VERSION 5.7 ;
  NOWIREEXTENSIONATPIN ON ;
  DIVIDERCHAR "/" ;
  BUSBITCHARS "[]" ;
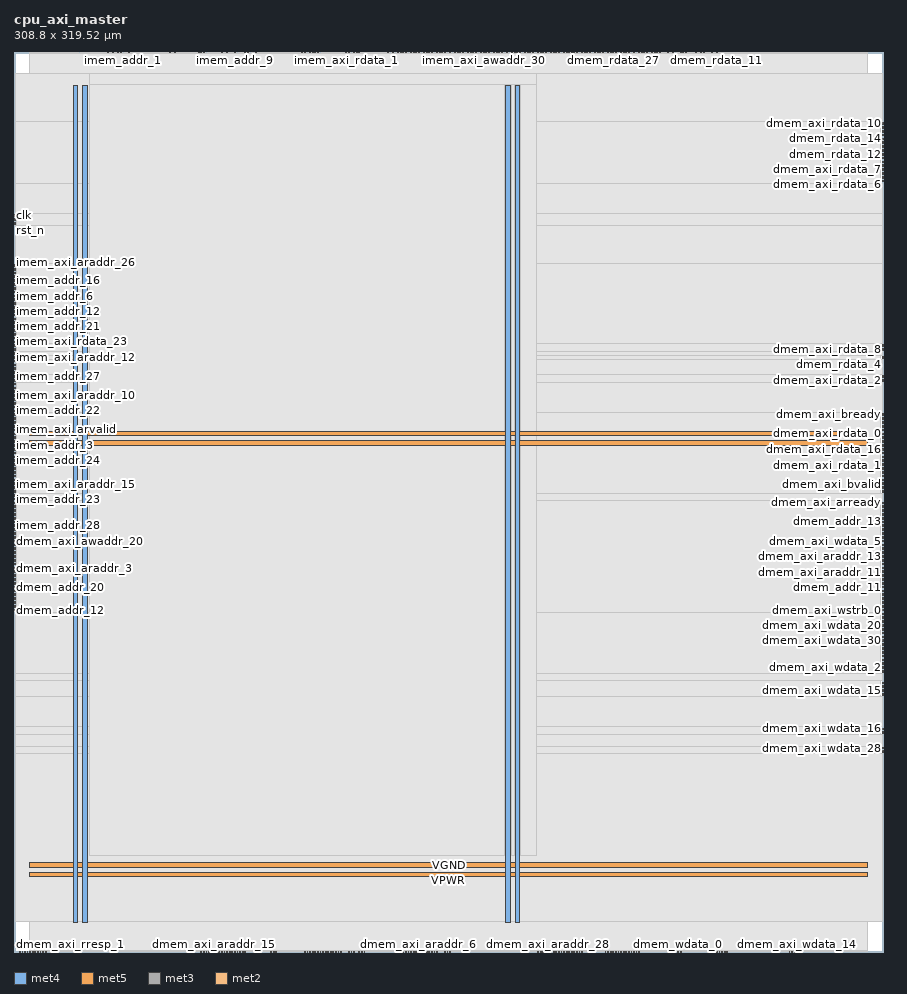
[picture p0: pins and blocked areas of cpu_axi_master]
MACRO cpu_axi_master
  CLASS BLOCK ;
  FOREIGN cpu_axi_master ;
  ORIGIN 0.000 0.000 ;
  SIZE 308.800 BY 319.520 ;
  PIN VGND
    DIRECTION INOUT ;
    USE GROUND ;
    PORT
      LAYER met4 ;
        RECT 24.340 10.640 25.940 307.600 ;
    END
    PORT
      LAYER met4 ;
        RECT 177.940 10.640 179.540 307.600 ;
    END
    PORT
      LAYER met5 ;
        RECT 5.520 30.030 303.140 31.630 ;
    END
    PORT
      LAYER met5 ;
        RECT 5.520 183.210 303.140 184.810 ;
    END
  END VGND
  PIN VPWR
    DIRECTION INOUT ;
    USE POWER ;
    PORT
      LAYER met4 ;
        RECT 21.040 10.640 22.640 307.600 ;
    END
    PORT
      LAYER met4 ;
        RECT 174.640 10.640 176.240 307.600 ;
    END
    PORT
      LAYER met5 ;
        RECT 5.520 26.730 303.140 28.330 ;
    END
    PORT
      LAYER met5 ;
        RECT 5.520 179.910 303.140 181.510 ;
    END
  END VPWR
  PIN clk
    DIRECTION INPUT ;
    USE SIGNAL ;
    ANTENNAGATEAREA 1.286700 ;
    ANTENNADIFFAREA 0.434700 ;
    PORT
      LAYER met3 ;
        RECT 0.000 261.160 0.600 261.760 ;
    END
  END clk
  PIN dmem_addr_0
    DIRECTION INPUT ;
    USE SIGNAL ;
    ANTENNAGATEAREA 0.647700 ;
    ANTENNADIFFAREA 0.434700 ;
    PORT
      LAYER met2 ;
        RECT 115.090 0.000 115.370 0.280 ;
    END
  END dmem_addr_0
  PIN dmem_addr_1
    DIRECTION INPUT ;
    USE SIGNAL ;
    ANTENNAGATEAREA 0.647700 ;
    ANTENNADIFFAREA 0.434700 ;
    PORT
      LAYER met2 ;
        RECT 105.890 0.000 106.170 0.280 ;
    END
  END dmem_addr_1
  PIN dmem_addr_10
    DIRECTION INPUT ;
    USE SIGNAL ;
    ANTENNAGATEAREA 0.647700 ;
    ANTENNADIFFAREA 0.434700 ;
    PORT
      LAYER met2 ;
        RECT 92.090 0.000 92.370 0.280 ;
    END
  END dmem_addr_10
  PIN dmem_addr_11
    DIRECTION INPUT ;
    USE SIGNAL ;
    ANTENNAGATEAREA 0.647700 ;
    ANTENNADIFFAREA 0.434700 ;
    PORT
      LAYER met3 ;
        RECT 308.200 129.240 308.800 129.840 ;
    END
  END dmem_addr_11
  PIN dmem_addr_12
    DIRECTION INPUT ;
    USE SIGNAL ;
    ANTENNAGATEAREA 0.647700 ;
    ANTENNADIFFAREA 0.434700 ;
    PORT
      LAYER met3 ;
        RECT 0.000 121.080 0.600 121.680 ;
    END
  END dmem_addr_12
  PIN dmem_addr_13
    DIRECTION INPUT ;
    USE SIGNAL ;
    ANTENNAGATEAREA 0.647700 ;
    ANTENNADIFFAREA 0.434700 ;
    PORT
      LAYER met3 ;
        RECT 308.200 152.360 308.800 152.960 ;
    END
  END dmem_addr_13
  PIN dmem_addr_14
    DIRECTION INPUT ;
    USE SIGNAL ;
    ANTENNAGATEAREA 0.647700 ;
    ANTENNADIFFAREA 0.434700 ;
    PORT
      LAYER met2 ;
        RECT 66.330 0.000 66.610 0.280 ;
    END
  END dmem_addr_14
  PIN dmem_addr_15
    DIRECTION INPUT ;
    USE SIGNAL ;
    ANTENNAGATEAREA 0.647700 ;
    ANTENNADIFFAREA 0.434700 ;
    PORT
      LAYER met2 ;
        RECT 73.690 0.000 73.970 0.280 ;
    END
  END dmem_addr_15
  PIN dmem_addr_16
    DIRECTION INPUT ;
    USE SIGNAL ;
    ANTENNAGATEAREA 0.647700 ;
    ANTENNADIFFAREA 0.434700 ;
    PORT
      LAYER met2 ;
        RECT 76.450 0.000 76.730 0.280 ;
    END
  END dmem_addr_16
  PIN dmem_addr_17
    DIRECTION INPUT ;
    USE SIGNAL ;
    ANTENNAGATEAREA 0.647700 ;
    ANTENNADIFFAREA 0.434700 ;
    PORT
      LAYER met2 ;
        RECT 109.570 0.000 109.850 0.280 ;
    END
  END dmem_addr_17
  PIN dmem_addr_18
    DIRECTION INPUT ;
    USE SIGNAL ;
    ANTENNAGATEAREA 0.647700 ;
    ANTENNADIFFAREA 0.434700 ;
    PORT
      LAYER met2 ;
        RECT 104.970 0.000 105.250 0.280 ;
    END
  END dmem_addr_18
  PIN dmem_addr_19
    DIRECTION INPUT ;
    USE SIGNAL ;
    ANTENNAGATEAREA 0.647700 ;
    ANTENNADIFFAREA 0.434700 ;
    PORT
      LAYER met2 ;
        RECT 123.370 0.000 123.650 0.280 ;
    END
  END dmem_addr_19
  PIN dmem_addr_2
    DIRECTION INPUT ;
    USE SIGNAL ;
    ANTENNAGATEAREA 0.647700 ;
    ANTENNADIFFAREA 0.434700 ;
    PORT
      LAYER met2 ;
        RECT 141.770 0.000 142.050 0.280 ;
    END
  END dmem_addr_2
  PIN dmem_addr_20
    DIRECTION INPUT ;
    USE SIGNAL ;
    ANTENNAGATEAREA 0.647700 ;
    ANTENNADIFFAREA 0.434700 ;
    PORT
      LAYER met3 ;
        RECT 0.000 129.240 0.600 129.840 ;
    END
  END dmem_addr_20
  PIN dmem_addr_21
    DIRECTION INPUT ;
    USE SIGNAL ;
    ANTENNAGATEAREA 0.647700 ;
    ANTENNADIFFAREA 0.434700 ;
    PORT
      LAYER met2 ;
        RECT 145.450 0.000 145.730 0.280 ;
    END
  END dmem_addr_21
  PIN dmem_addr_22
    DIRECTION INPUT ;
    USE SIGNAL ;
    ANTENNAGATEAREA 0.647700 ;
    ANTENNADIFFAREA 0.434700 ;
    PORT
      LAYER met2 ;
        RECT 137.170 0.000 137.450 0.280 ;
    END
  END dmem_addr_22
  PIN dmem_addr_23
    DIRECTION INPUT ;
    USE SIGNAL ;
    ANTENNAGATEAREA 0.647700 ;
    ANTENNADIFFAREA 0.434700 ;
    PORT
      LAYER met2 ;
        RECT 77.370 0.000 77.650 0.280 ;
    END
  END dmem_addr_23
  PIN dmem_addr_24
    DIRECTION INPUT ;
    USE SIGNAL ;
    ANTENNAGATEAREA 0.647700 ;
    ANTENNADIFFAREA 0.434700 ;
    PORT
      LAYER met2 ;
        RECT 146.370 0.000 146.650 0.280 ;
    END
  END dmem_addr_24
  PIN dmem_addr_25
    DIRECTION INPUT ;
    USE SIGNAL ;
    ANTENNAGATEAREA 0.647700 ;
    ANTENNADIFFAREA 0.434700 ;
    PORT
      LAYER met2 ;
        RECT 119.690 0.000 119.970 0.280 ;
    END
  END dmem_addr_25
  PIN dmem_addr_26
    DIRECTION INPUT ;
    USE SIGNAL ;
    ANTENNAGATEAREA 0.647700 ;
    ANTENNADIFFAREA 0.434700 ;
    PORT
      LAYER met2 ;
        RECT 201.570 0.000 201.850 0.280 ;
    END
  END dmem_addr_26
  PIN dmem_addr_27
    DIRECTION INPUT ;
    USE SIGNAL ;
    ANTENNAGATEAREA 0.647700 ;
    ANTENNADIFFAREA 0.434700 ;
    PORT
      LAYER met2 ;
        RECT 194.210 0.000 194.490 0.280 ;
    END
  END dmem_addr_27
  PIN dmem_addr_28
    DIRECTION INPUT ;
    USE SIGNAL ;
    ANTENNAGATEAREA 0.647700 ;
    ANTENNADIFFAREA 0.434700 ;
    PORT
      LAYER met2 ;
        RECT 188.690 0.000 188.970 0.280 ;
    END
  END dmem_addr_28
  PIN dmem_addr_29
    DIRECTION INPUT ;
    USE SIGNAL ;
    ANTENNAGATEAREA 0.647700 ;
    ANTENNADIFFAREA 0.434700 ;
    PORT
      LAYER met2 ;
        RECT 199.730 0.000 200.010 0.280 ;
    END
  END dmem_addr_29
  PIN dmem_addr_3
    DIRECTION INPUT ;
    USE SIGNAL ;
    ANTENNAGATEAREA 0.647700 ;
    ANTENNADIFFAREA 0.434700 ;
    PORT
      LAYER met3 ;
        RECT 0.000 130.600 0.600 131.200 ;
    END
  END dmem_addr_3
  PIN dmem_addr_30
    DIRECTION INPUT ;
    USE SIGNAL ;
    ANTENNAGATEAREA 0.647700 ;
    ANTENNADIFFAREA 0.434700 ;
    PORT
      LAYER met2 ;
        RECT 200.650 0.000 200.930 0.280 ;
    END
  END dmem_addr_30
  PIN dmem_addr_31
    DIRECTION INPUT ;
    USE SIGNAL ;
    ANTENNAGATEAREA 0.647700 ;
    ANTENNADIFFAREA 0.434700 ;
    PORT
      LAYER met2 ;
        RECT 187.770 0.000 188.050 0.280 ;
    END
  END dmem_addr_31
  PIN dmem_addr_4
    DIRECTION INPUT ;
    USE SIGNAL ;
    ANTENNAGATEAREA 0.647700 ;
    ANTENNADIFFAREA 0.434700 ;
    PORT
      LAYER met2 ;
        RECT 75.530 0.000 75.810 0.280 ;
    END
  END dmem_addr_4
  PIN dmem_addr_5
    DIRECTION INPUT ;
    USE SIGNAL ;
    ANTENNAGATEAREA 0.647700 ;
    ANTENNADIFFAREA 0.434700 ;
    PORT
      LAYER met2 ;
        RECT 80.130 0.000 80.410 0.280 ;
    END
  END dmem_addr_5
  PIN dmem_addr_6
    DIRECTION INPUT ;
    USE SIGNAL ;
    ANTENNAGATEAREA 0.647700 ;
    ANTENNADIFFAREA 0.434700 ;
    PORT
      LAYER met2 ;
        RECT 142.690 0.000 142.970 0.280 ;
    END
  END dmem_addr_6
  PIN dmem_addr_7
    DIRECTION INPUT ;
    USE SIGNAL ;
    ANTENNAGATEAREA 0.647700 ;
    ANTENNADIFFAREA 0.434700 ;
    PORT
      LAYER met2 ;
        RECT 110.490 0.000 110.770 0.280 ;
    END
  END dmem_addr_7
  PIN dmem_addr_8
    DIRECTION INPUT ;
    USE SIGNAL ;
    ANTENNAGATEAREA 0.647700 ;
    ANTENNADIFFAREA 0.434700 ;
    PORT
      LAYER met3 ;
        RECT 0.000 123.800 0.600 124.400 ;
    END
  END dmem_addr_8
  PIN dmem_addr_9
    DIRECTION INPUT ;
    USE SIGNAL ;
    ANTENNAGATEAREA 0.647700 ;
    ANTENNADIFFAREA 0.434700 ;
    PORT
      LAYER met2 ;
        RECT 153.730 0.000 154.010 0.280 ;
    END
  END dmem_addr_9
  PIN dmem_axi_araddr_0
    DIRECTION OUTPUT ;
    USE SIGNAL ;
    ANTENNAGATEAREA 0.434700 ;
    ANTENNADIFFAREA 1.137600 ;
    PORT
      LAYER met2 ;
        RECT 114.170 0.000 114.450 0.280 ;
    END
  END dmem_axi_araddr_0
  PIN dmem_axi_araddr_1
    DIRECTION OUTPUT ;
    USE SIGNAL ;
    ANTENNAGATEAREA 0.434700 ;
    ANTENNADIFFAREA 1.137600 ;
    PORT
      LAYER met2 ;
        RECT 106.810 0.000 107.090 0.280 ;
    END
  END dmem_axi_araddr_1
  PIN dmem_axi_araddr_10
    DIRECTION OUTPUT ;
    USE SIGNAL ;
    ANTENNAGATEAREA 0.434700 ;
    ANTENNADIFFAREA 1.137600 ;
    PORT
      LAYER met2 ;
        RECT 91.170 0.000 91.450 0.280 ;
    END
  END dmem_axi_araddr_10
  PIN dmem_axi_araddr_11
    DIRECTION OUTPUT ;
    USE SIGNAL ;
    ANTENNAGATEAREA 0.434700 ;
    ANTENNADIFFAREA 1.137600 ;
    PORT
      LAYER met3 ;
        RECT 308.200 131.960 308.800 132.560 ;
    END
  END dmem_axi_araddr_11
  PIN dmem_axi_araddr_12
    DIRECTION OUTPUT ;
    USE SIGNAL ;
    ANTENNAGATEAREA 0.434700 ;
    ANTENNADIFFAREA 1.137600 ;
    PORT
      LAYER met3 ;
        RECT 0.000 125.160 0.600 125.760 ;
    END
  END dmem_axi_araddr_12
  PIN dmem_axi_araddr_13
    DIRECTION OUTPUT ;
    USE SIGNAL ;
    ANTENNAGATEAREA 0.434700 ;
    ANTENNADIFFAREA 1.137600 ;
    PORT
      LAYER met3 ;
        RECT 308.200 140.120 308.800 140.720 ;
    END
  END dmem_axi_araddr_13
  PIN dmem_axi_araddr_14
    DIRECTION OUTPUT ;
    USE SIGNAL ;
    ANTENNAGATEAREA 0.434700 ;
    ANTENNADIFFAREA 1.137600 ;
    PORT
      LAYER met2 ;
        RECT 67.250 0.000 67.530 0.280 ;
    END
  END dmem_axi_araddr_14
  PIN dmem_axi_araddr_15
    DIRECTION OUTPUT ;
    USE SIGNAL ;
    ANTENNAGATEAREA 0.434700 ;
    ANTENNADIFFAREA 1.137600 ;
    PORT
      LAYER met2 ;
        RECT 70.930 0.000 71.210 0.280 ;
    END
  END dmem_axi_araddr_15
  PIN dmem_axi_araddr_16
    DIRECTION OUTPUT ;
    USE SIGNAL ;
    ANTENNAGATEAREA 0.434700 ;
    ANTENNADIFFAREA 1.137600 ;
    PORT
      LAYER met2 ;
        RECT 69.090 0.000 69.370 0.280 ;
    END
  END dmem_axi_araddr_16
  PIN dmem_axi_araddr_17
    DIRECTION OUTPUT ;
    USE SIGNAL ;
    ANTENNAGATEAREA 0.434700 ;
    ANTENNADIFFAREA 1.137600 ;
    PORT
      LAYER met2 ;
        RECT 111.410 0.000 111.690 0.280 ;
    END
  END dmem_axi_araddr_17
  PIN dmem_axi_araddr_18
    DIRECTION OUTPUT ;
    USE SIGNAL ;
    ANTENNAGATEAREA 0.434700 ;
    ANTENNADIFFAREA 1.137600 ;
    PORT
      LAYER met2 ;
        RECT 103.130 0.000 103.410 0.280 ;
    END
  END dmem_axi_araddr_18
  PIN dmem_axi_araddr_19
    DIRECTION OUTPUT ;
    USE SIGNAL ;
    ANTENNAGATEAREA 0.434700 ;
    ANTENNADIFFAREA 1.137600 ;
    PORT
      LAYER met2 ;
        RECT 124.290 0.000 124.570 0.280 ;
    END
  END dmem_axi_araddr_19
  PIN dmem_axi_araddr_2
    DIRECTION OUTPUT ;
    USE SIGNAL ;
    ANTENNAGATEAREA 0.434700 ;
    ANTENNADIFFAREA 1.137600 ;
    PORT
      LAYER met2 ;
        RECT 140.850 0.000 141.130 0.280 ;
    END
  END dmem_axi_araddr_2
  PIN dmem_axi_araddr_20
    DIRECTION OUTPUT ;
    USE SIGNAL ;
    ANTENNAGATEAREA 0.434700 ;
    ANTENNADIFFAREA 1.137600 ;
    PORT
      LAYER met3 ;
        RECT 0.000 144.200 0.600 144.800 ;
    END
  END dmem_axi_araddr_20
  PIN dmem_axi_araddr_21
    DIRECTION OUTPUT ;
    USE SIGNAL ;
    ANTENNAGATEAREA 0.434700 ;
    ANTENNADIFFAREA 1.137600 ;
    PORT
      LAYER met2 ;
        RECT 150.050 0.000 150.330 0.280 ;
    END
  END dmem_axi_araddr_21
  PIN dmem_axi_araddr_22
    DIRECTION OUTPUT ;
    USE SIGNAL ;
    ANTENNAGATEAREA 0.434700 ;
    ANTENNADIFFAREA 1.137600 ;
    PORT
      LAYER met2 ;
        RECT 138.090 0.000 138.370 0.280 ;
    END
  END dmem_axi_araddr_22
  PIN dmem_axi_araddr_23
    DIRECTION OUTPUT ;
    USE SIGNAL ;
    ANTENNAGATEAREA 0.434700 ;
    ANTENNADIFFAREA 1.137600 ;
    PORT
      LAYER met2 ;
        RECT 78.290 0.000 78.570 0.280 ;
    END
  END dmem_axi_araddr_23
  PIN dmem_axi_araddr_24
    DIRECTION OUTPUT ;
    USE SIGNAL ;
    ANTENNAGATEAREA 0.434700 ;
    ANTENNADIFFAREA 1.137600 ;
    PORT
      LAYER met2 ;
        RECT 149.130 0.000 149.410 0.280 ;
    END
  END dmem_axi_araddr_24
  PIN dmem_axi_araddr_25
    DIRECTION OUTPUT ;
    USE SIGNAL ;
    ANTENNAGATEAREA 0.434700 ;
    ANTENNADIFFAREA 1.137600 ;
    PORT
      LAYER met2 ;
        RECT 120.610 0.000 120.890 0.280 ;
    END
  END dmem_axi_araddr_25
  PIN dmem_axi_araddr_26
    DIRECTION OUTPUT ;
    USE SIGNAL ;
    ANTENNAGATEAREA 0.434700 ;
    ANTENNADIFFAREA 1.137600 ;
    PORT
      LAYER met2 ;
        RECT 186.850 0.000 187.130 0.280 ;
    END
  END dmem_axi_araddr_26
  PIN dmem_axi_araddr_27
    DIRECTION OUTPUT ;
    USE SIGNAL ;
    ANTENNAGATEAREA 0.434700 ;
    ANTENNADIFFAREA 1.137600 ;
    PORT
      LAYER met2 ;
        RECT 196.050 0.000 196.330 0.280 ;
    END
  END dmem_axi_araddr_27
  PIN dmem_axi_araddr_28
    DIRECTION OUTPUT ;
    USE SIGNAL ;
    ANTENNAGATEAREA 0.434700 ;
    ANTENNADIFFAREA 1.137600 ;
    PORT
      LAYER met2 ;
        RECT 189.610 0.000 189.890 0.280 ;
    END
  END dmem_axi_araddr_28
  PIN dmem_axi_araddr_29
    DIRECTION OUTPUT ;
    USE SIGNAL ;
    ANTENNAGATEAREA 0.434700 ;
    ANTENNADIFFAREA 1.137600 ;
    PORT
      LAYER met2 ;
        RECT 185.930 0.000 186.210 0.280 ;
    END
  END dmem_axi_araddr_29
  PIN dmem_axi_araddr_3
    DIRECTION OUTPUT ;
    USE SIGNAL ;
    ANTENNAGATEAREA 0.434700 ;
    ANTENNADIFFAREA 1.137600 ;
    PORT
      LAYER met3 ;
        RECT 0.000 133.320 0.600 133.920 ;
    END
  END dmem_axi_araddr_3
  PIN dmem_axi_araddr_30
    DIRECTION OUTPUT ;
    USE SIGNAL ;
    ANTENNAGATEAREA 0.434700 ;
    ANTENNADIFFAREA 1.137600 ;
    PORT
      LAYER met2 ;
        RECT 190.530 0.000 190.810 0.280 ;
    END
  END dmem_axi_araddr_30
  PIN dmem_axi_araddr_31
    DIRECTION OUTPUT ;
    USE SIGNAL ;
    ANTENNAGATEAREA 0.434700 ;
    ANTENNADIFFAREA 1.137600 ;
    PORT
      LAYER met2 ;
        RECT 196.970 0.000 197.250 0.280 ;
    END
  END dmem_axi_araddr_31
  PIN dmem_axi_araddr_4
    DIRECTION OUTPUT ;
    USE SIGNAL ;
    ANTENNAGATEAREA 0.434700 ;
    ANTENNADIFFAREA 1.137600 ;
    PORT
      LAYER met2 ;
        RECT 72.770 0.000 73.050 0.280 ;
    END
  END dmem_axi_araddr_4
  PIN dmem_axi_araddr_5
    DIRECTION OUTPUT ;
    USE SIGNAL ;
    ANTENNAGATEAREA 0.434700 ;
    ANTENNADIFFAREA 1.137600 ;
    PORT
      LAYER met2 ;
        RECT 81.970 0.000 82.250 0.280 ;
    END
  END dmem_axi_araddr_5
  PIN dmem_axi_araddr_6
    DIRECTION OUTPUT ;
    USE SIGNAL ;
    ANTENNAGATEAREA 0.434700 ;
    ANTENNADIFFAREA 1.137600 ;
    PORT
      LAYER met2 ;
        RECT 143.610 0.000 143.890 0.280 ;
    END
  END dmem_axi_araddr_6
  PIN dmem_axi_araddr_7
    DIRECTION OUTPUT ;
    USE SIGNAL ;
    ANTENNAGATEAREA 0.434700 ;
    ANTENNADIFFAREA 1.137600 ;
    PORT
      LAYER met2 ;
        RECT 112.330 0.000 112.610 0.280 ;
    END
  END dmem_axi_araddr_7
  PIN dmem_axi_araddr_8
    DIRECTION OUTPUT ;
    USE SIGNAL ;
    ANTENNAGATEAREA 0.434700 ;
    ANTENNADIFFAREA 1.137600 ;
    PORT
      LAYER met3 ;
        RECT 0.000 136.040 0.600 136.640 ;
    END
  END dmem_axi_araddr_8
  PIN dmem_axi_araddr_9
    DIRECTION OUTPUT ;
    USE SIGNAL ;
    ANTENNAGATEAREA 0.434700 ;
    ANTENNADIFFAREA 1.137600 ;
    PORT
      LAYER met2 ;
        RECT 152.810 0.000 153.090 0.280 ;
    END
  END dmem_axi_araddr_9
  PIN dmem_axi_arready
    DIRECTION INPUT ;
    USE SIGNAL ;
    ANTENNAGATEAREA 0.647700 ;
    ANTENNADIFFAREA 0.434700 ;
    PORT
      LAYER met3 ;
        RECT 308.200 159.160 308.800 159.760 ;
    END
  END dmem_axi_arready
  PIN dmem_axi_arvalid
    DIRECTION OUTPUT ;
    USE SIGNAL ;
    ANTENNAGATEAREA 0.434700 ;
    ANTENNADIFFAREA 1.137600 ;
    PORT
      LAYER met3 ;
        RECT 308.200 157.800 308.800 158.400 ;
    END
  END dmem_axi_arvalid
  PIN dmem_axi_awaddr_0
    DIRECTION OUTPUT ;
    USE SIGNAL ;
    ANTENNAGATEAREA 0.434700 ;
    ANTENNADIFFAREA 1.137600 ;
    PORT
      LAYER met2 ;
        RECT 116.010 0.000 116.290 0.280 ;
    END
  END dmem_axi_awaddr_0
  PIN dmem_axi_awaddr_1
    DIRECTION OUTPUT ;
    USE SIGNAL ;
    ANTENNAGATEAREA 0.434700 ;
    ANTENNADIFFAREA 1.137600 ;
    PORT
      LAYER met2 ;
        RECT 107.730 0.000 108.010 0.280 ;
    END
  END dmem_axi_awaddr_1
  PIN dmem_axi_awaddr_10
    DIRECTION OUTPUT ;
    USE SIGNAL ;
    ANTENNAGATEAREA 0.434700 ;
    ANTENNADIFFAREA 1.137600 ;
    PORT
      LAYER met2 ;
        RECT 93.010 0.000 93.290 0.280 ;
    END
  END dmem_axi_awaddr_10
  PIN dmem_axi_awaddr_11
    DIRECTION OUTPUT ;
    USE SIGNAL ;
    ANTENNAGATEAREA 0.434700 ;
    ANTENNADIFFAREA 1.137600 ;
    PORT
      LAYER met3 ;
        RECT 308.200 130.600 308.800 131.200 ;
    END
  END dmem_axi_awaddr_11
  PIN dmem_axi_awaddr_12
    DIRECTION OUTPUT ;
    USE SIGNAL ;
    ANTENNAGATEAREA 0.434700 ;
    ANTENNADIFFAREA 1.137600 ;
    PORT
      LAYER met3 ;
        RECT 0.000 126.520 0.600 127.120 ;
    END
  END dmem_axi_awaddr_12
  PIN dmem_axi_awaddr_13
    DIRECTION OUTPUT ;
    USE SIGNAL ;
    ANTENNAGATEAREA 0.434700 ;
    ANTENNADIFFAREA 1.137600 ;
    PORT
      LAYER met3 ;
        RECT 308.200 138.760 308.800 139.360 ;
    END
  END dmem_axi_awaddr_13
  PIN dmem_axi_awaddr_14
    DIRECTION OUTPUT ;
    USE SIGNAL ;
    ANTENNAGATEAREA 0.434700 ;
    ANTENNADIFFAREA 1.137600 ;
    PORT
      LAYER met2 ;
        RECT 68.170 0.000 68.450 0.280 ;
    END
  END dmem_axi_awaddr_14
  PIN dmem_axi_awaddr_15
    DIRECTION OUTPUT ;
    USE SIGNAL ;
    ANTENNAGATEAREA 0.434700 ;
    ANTENNADIFFAREA 1.137600 ;
    PORT
      LAYER met2 ;
        RECT 70.010 0.000 70.290 0.280 ;
    END
  END dmem_axi_awaddr_15
  PIN dmem_axi_awaddr_16
    DIRECTION OUTPUT ;
    USE SIGNAL ;
    ANTENNAGATEAREA 0.434700 ;
    ANTENNADIFFAREA 1.137600 ;
    PORT
      LAYER met2 ;
        RECT 71.850 0.000 72.130 0.280 ;
    END
  END dmem_axi_awaddr_16
  PIN dmem_axi_awaddr_17
    DIRECTION OUTPUT ;
    USE SIGNAL ;
    ANTENNAGATEAREA 0.434700 ;
    ANTENNADIFFAREA 1.137600 ;
    PORT
      LAYER met2 ;
        RECT 108.650 0.000 108.930 0.280 ;
    END
  END dmem_axi_awaddr_17
  PIN dmem_axi_awaddr_18
    DIRECTION OUTPUT ;
    USE SIGNAL ;
    ANTENNAGATEAREA 0.434700 ;
    ANTENNADIFFAREA 1.137600 ;
    PORT
      LAYER met2 ;
        RECT 104.050 0.000 104.330 0.280 ;
    END
  END dmem_axi_awaddr_18
  PIN dmem_axi_awaddr_19
    DIRECTION OUTPUT ;
    USE SIGNAL ;
    ANTENNAGATEAREA 0.434700 ;
    ANTENNADIFFAREA 1.137600 ;
    PORT
      LAYER met2 ;
        RECT 122.450 0.000 122.730 0.280 ;
    END
  END dmem_axi_awaddr_19
  PIN dmem_axi_awaddr_2
    DIRECTION OUTPUT ;
    USE SIGNAL ;
    ANTENNAGATEAREA 0.434700 ;
    ANTENNADIFFAREA 1.137600 ;
    PORT
      LAYER met2 ;
        RECT 139.930 0.000 140.210 0.280 ;
    END
  END dmem_axi_awaddr_2
  PIN dmem_axi_awaddr_20
    DIRECTION OUTPUT ;
    USE SIGNAL ;
    ANTENNAGATEAREA 0.434700 ;
    ANTENNADIFFAREA 1.137600 ;
    PORT
      LAYER met3 ;
        RECT 0.000 145.560 0.600 146.160 ;
    END
  END dmem_axi_awaddr_20
  PIN dmem_axi_awaddr_21
    DIRECTION OUTPUT ;
    USE SIGNAL ;
    ANTENNAGATEAREA 0.434700 ;
    ANTENNADIFFAREA 1.137600 ;
    PORT
      LAYER met2 ;
        RECT 147.290 0.000 147.570 0.280 ;
    END
  END dmem_axi_awaddr_21
  PIN dmem_axi_awaddr_22
    DIRECTION OUTPUT ;
    USE SIGNAL ;
    ANTENNAGATEAREA 0.434700 ;
    ANTENNADIFFAREA 1.137600 ;
    PORT
      LAYER met2 ;
        RECT 139.010 0.000 139.290 0.280 ;
    END
  END dmem_axi_awaddr_22
  PIN dmem_axi_awaddr_23
    DIRECTION OUTPUT ;
    USE SIGNAL ;
    ANTENNAGATEAREA 0.434700 ;
    ANTENNADIFFAREA 1.137600 ;
    PORT
      LAYER met2 ;
        RECT 79.210 0.000 79.490 0.280 ;
    END
  END dmem_axi_awaddr_23
  PIN dmem_axi_awaddr_24
    DIRECTION OUTPUT ;
    USE SIGNAL ;
    ANTENNAGATEAREA 0.434700 ;
    ANTENNADIFFAREA 1.137600 ;
    PORT
      LAYER met2 ;
        RECT 148.210 0.000 148.490 0.280 ;
    END
  END dmem_axi_awaddr_24
  PIN dmem_axi_awaddr_25
    DIRECTION OUTPUT ;
    USE SIGNAL ;
    ANTENNAGATEAREA 0.434700 ;
    ANTENNADIFFAREA 1.137600 ;
    PORT
      LAYER met2 ;
        RECT 118.770 0.000 119.050 0.280 ;
    END
  END dmem_axi_awaddr_25
  PIN dmem_axi_awaddr_26
    DIRECTION OUTPUT ;
    USE SIGNAL ;
    ANTENNAGATEAREA 0.434700 ;
    ANTENNADIFFAREA 1.137600 ;
    PORT
      LAYER met2 ;
        RECT 191.450 0.000 191.730 0.280 ;
    END
  END dmem_axi_awaddr_26
  PIN dmem_axi_awaddr_27
    DIRECTION OUTPUT ;
    USE SIGNAL ;
    ANTENNAGATEAREA 0.434700 ;
    ANTENNADIFFAREA 1.137600 ;
    PORT
      LAYER met2 ;
        RECT 192.370 0.000 192.650 0.280 ;
    END
  END dmem_axi_awaddr_27
  PIN dmem_axi_awaddr_28
    DIRECTION OUTPUT ;
    USE SIGNAL ;
    ANTENNAGATEAREA 0.434700 ;
    ANTENNADIFFAREA 1.137600 ;
    PORT
      LAYER met2 ;
        RECT 197.890 0.000 198.170 0.280 ;
    END
  END dmem_axi_awaddr_28
  PIN dmem_axi_awaddr_29
    DIRECTION OUTPUT ;
    USE SIGNAL ;
    ANTENNAGATEAREA 0.434700 ;
    ANTENNADIFFAREA 1.137600 ;
    PORT
      LAYER met2 ;
        RECT 195.130 0.000 195.410 0.280 ;
    END
  END dmem_axi_awaddr_29
  PIN dmem_axi_awaddr_3
    DIRECTION OUTPUT ;
    USE SIGNAL ;
    ANTENNAGATEAREA 0.434700 ;
    ANTENNADIFFAREA 1.137600 ;
    PORT
      LAYER met3 ;
        RECT 0.000 134.680 0.600 135.280 ;
    END
  END dmem_axi_awaddr_3
  PIN dmem_axi_awaddr_30
    DIRECTION OUTPUT ;
    USE SIGNAL ;
    ANTENNAGATEAREA 0.434700 ;
    ANTENNADIFFAREA 1.137600 ;
    PORT
      LAYER met2 ;
        RECT 193.290 0.000 193.570 0.280 ;
    END
  END dmem_axi_awaddr_30
  PIN dmem_axi_awaddr_31
    DIRECTION OUTPUT ;
    USE SIGNAL ;
    ANTENNAGATEAREA 0.434700 ;
    ANTENNADIFFAREA 1.137600 ;
    PORT
      LAYER met2 ;
        RECT 198.810 0.000 199.090 0.280 ;
    END
  END dmem_axi_awaddr_31
  PIN dmem_axi_awaddr_4
    DIRECTION OUTPUT ;
    USE SIGNAL ;
    ANTENNAGATEAREA 0.434700 ;
    ANTENNADIFFAREA 1.137600 ;
    PORT
      LAYER met2 ;
        RECT 74.610 0.000 74.890 0.280 ;
    END
  END dmem_axi_awaddr_4
  PIN dmem_axi_awaddr_5
    DIRECTION OUTPUT ;
    USE SIGNAL ;
    ANTENNAGATEAREA 0.434700 ;
    ANTENNADIFFAREA 1.137600 ;
    PORT
      LAYER met2 ;
        RECT 81.050 0.000 81.330 0.280 ;
    END
  END dmem_axi_awaddr_5
  PIN dmem_axi_awaddr_6
    DIRECTION OUTPUT ;
    USE SIGNAL ;
    ANTENNAGATEAREA 0.434700 ;
    ANTENNADIFFAREA 1.137600 ;
    PORT
      LAYER met2 ;
        RECT 144.530 0.000 144.810 0.280 ;
    END
  END dmem_axi_awaddr_6
  PIN dmem_axi_awaddr_7
    DIRECTION OUTPUT ;
    USE SIGNAL ;
    ANTENNAGATEAREA 0.434700 ;
    ANTENNADIFFAREA 1.137600 ;
    PORT
      LAYER met2 ;
        RECT 113.250 0.000 113.530 0.280 ;
    END
  END dmem_axi_awaddr_7
  PIN dmem_axi_awaddr_8
    DIRECTION OUTPUT ;
    USE SIGNAL ;
    ANTENNAGATEAREA 0.434700 ;
    ANTENNADIFFAREA 1.137600 ;
    PORT
      LAYER met3 ;
        RECT 0.000 138.760 0.600 139.360 ;
    END
  END dmem_axi_awaddr_8
  PIN dmem_axi_awaddr_9
    DIRECTION OUTPUT ;
    USE SIGNAL ;
    ANTENNAGATEAREA 0.434700 ;
    ANTENNADIFFAREA 1.137600 ;
    PORT
      LAYER met2 ;
        RECT 154.650 0.000 154.930 0.280 ;
    END
  END dmem_axi_awaddr_9
  PIN dmem_axi_awready
    DIRECTION INPUT ;
    USE SIGNAL ;
    ANTENNAGATEAREA 0.647700 ;
    ANTENNADIFFAREA 0.434700 ;
    PORT
      LAYER met3 ;
        RECT 308.200 153.720 308.800 154.320 ;
    END
  END dmem_axi_awready
  PIN dmem_axi_awvalid
    DIRECTION OUTPUT ;
    USE SIGNAL ;
    ANTENNAGATEAREA 0.434700 ;
    ANTENNADIFFAREA 1.137600 ;
    PORT
      LAYER met3 ;
        RECT 308.200 155.080 308.800 155.680 ;
    END
  END dmem_axi_awvalid
  PIN dmem_axi_bready
    DIRECTION OUTPUT ;
    USE SIGNAL ;
    ANTENNAGATEAREA 0.434700 ;
    ANTENNADIFFAREA 1.137600 ;
    PORT
      LAYER met3 ;
        RECT 308.200 190.440 308.800 191.040 ;
    END
  END dmem_axi_bready
  PIN dmem_axi_bresp_0
    DIRECTION INPUT ;
    USE SIGNAL ;
    PORT
      LAYER met2 ;
        RECT 1.930 0.000 2.210 0.280 ;
    END
  END dmem_axi_bresp_0
  PIN dmem_axi_bresp_1
    DIRECTION INPUT ;
    USE SIGNAL ;
    PORT
      LAYER met2 ;
        RECT 2.850 0.000 3.130 0.280 ;
    END
  END dmem_axi_bresp_1
  PIN dmem_axi_bvalid
    DIRECTION INPUT ;
    USE SIGNAL ;
    ANTENNAGATEAREA 0.647700 ;
    ANTENNADIFFAREA 0.434700 ;
    PORT
      LAYER met3 ;
        RECT 308.200 163.240 308.800 163.840 ;
    END
  END dmem_axi_bvalid
  PIN dmem_axi_rdata_0
    DIRECTION INPUT ;
    USE SIGNAL ;
    ANTENNAGATEAREA 0.647700 ;
    ANTENNADIFFAREA 0.434700 ;
    PORT
      LAYER met3 ;
        RECT 308.200 186.360 308.800 186.960 ;
    END
  END dmem_axi_rdata_0
  PIN dmem_axi_rdata_1
    DIRECTION INPUT ;
    USE SIGNAL ;
    ANTENNAGATEAREA 0.647700 ;
    ANTENNADIFFAREA 0.434700 ;
    PORT
      LAYER met3 ;
        RECT 308.200 170.040 308.800 170.640 ;
    END
  END dmem_axi_rdata_1
  PIN dmem_axi_rdata_10
    DIRECTION INPUT ;
    USE SIGNAL ;
    ANTENNAGATEAREA 0.647700 ;
    ANTENNADIFFAREA 0.434700 ;
    PORT
      LAYER met3 ;
        RECT 308.200 293.800 308.800 294.400 ;
    END
  END dmem_axi_rdata_10
  PIN dmem_axi_rdata_11
    DIRECTION INPUT ;
    USE SIGNAL ;
    ANTENNAGATEAREA 0.647700 ;
    ANTENNADIFFAREA 0.434700 ;
    PORT
      LAYER met2 ;
        RECT 247.570 319.240 247.850 319.520 ;
    END
  END dmem_axi_rdata_11
  PIN dmem_axi_rdata_12
    DIRECTION INPUT ;
    USE SIGNAL ;
    ANTENNAGATEAREA 0.647700 ;
    ANTENNADIFFAREA 0.434700 ;
    PORT
      LAYER met3 ;
        RECT 308.200 285.640 308.800 286.240 ;
    END
  END dmem_axi_rdata_12
  PIN dmem_axi_rdata_13
    DIRECTION INPUT ;
    USE SIGNAL ;
    ANTENNAGATEAREA 0.647700 ;
    ANTENNADIFFAREA 0.434700 ;
    PORT
      LAYER met3 ;
        RECT 308.200 284.280 308.800 284.880 ;
    END
  END dmem_axi_rdata_13
  PIN dmem_axi_rdata_14
    DIRECTION INPUT ;
    USE SIGNAL ;
    ANTENNAGATEAREA 0.647700 ;
    ANTENNADIFFAREA 0.434700 ;
    PORT
      LAYER met3 ;
        RECT 308.200 287.000 308.800 287.600 ;
    END
  END dmem_axi_rdata_14
  PIN dmem_axi_rdata_15
    DIRECTION INPUT ;
    USE SIGNAL ;
    ANTENNAGATEAREA 0.647700 ;
    ANTENNADIFFAREA 0.434700 ;
    PORT
      LAYER met3 ;
        RECT 308.200 278.840 308.800 279.440 ;
    END
  END dmem_axi_rdata_15
  PIN dmem_axi_rdata_16
    DIRECTION INPUT ;
    USE SIGNAL ;
    ANTENNAGATEAREA 0.647700 ;
    ANTENNADIFFAREA 0.434700 ;
    PORT
      LAYER met3 ;
        RECT 308.200 175.480 308.800 176.080 ;
    END
  END dmem_axi_rdata_16
  PIN dmem_axi_rdata_17
    DIRECTION INPUT ;
    USE SIGNAL ;
    ANTENNAGATEAREA 0.647700 ;
    ANTENNADIFFAREA 0.434700 ;
    PORT
      LAYER met3 ;
        RECT 308.200 164.600 308.800 165.200 ;
    END
  END dmem_axi_rdata_17
  PIN dmem_axi_rdata_18
    DIRECTION INPUT ;
    USE SIGNAL ;
    ANTENNAGATEAREA 0.647700 ;
    ANTENNADIFFAREA 0.434700 ;
    PORT
      LAYER met3 ;
        RECT 308.200 185.000 308.800 185.600 ;
    END
  END dmem_axi_rdata_18
  PIN dmem_axi_rdata_19
    DIRECTION INPUT ;
    USE SIGNAL ;
    ANTENNAGATEAREA 0.647700 ;
    ANTENNADIFFAREA 0.434700 ;
    PORT
      LAYER met3 ;
        RECT 308.200 178.200 308.800 178.800 ;
    END
  END dmem_axi_rdata_19
  PIN dmem_axi_rdata_2
    DIRECTION INPUT ;
    USE SIGNAL ;
    ANTENNAGATEAREA 0.647700 ;
    ANTENNADIFFAREA 0.434700 ;
    PORT
      LAYER met3 ;
        RECT 308.200 202.680 308.800 203.280 ;
    END
  END dmem_axi_rdata_2
  PIN dmem_axi_rdata_20
    DIRECTION INPUT ;
    USE SIGNAL ;
    ANTENNAGATEAREA 0.647700 ;
    ANTENNADIFFAREA 0.434700 ;
    PORT
      LAYER met2 ;
        RECT 229.170 319.240 229.450 319.520 ;
    END
  END dmem_axi_rdata_20
  PIN dmem_axi_rdata_21
    DIRECTION INPUT ;
    USE SIGNAL ;
    ANTENNAGATEAREA 0.647700 ;
    ANTENNADIFFAREA 0.434700 ;
    PORT
      LAYER met2 ;
        RECT 216.290 319.240 216.570 319.520 ;
    END
  END dmem_axi_rdata_21
  PIN dmem_axi_rdata_22
    DIRECTION INPUT ;
    USE SIGNAL ;
    ANTENNAGATEAREA 0.647700 ;
    ANTENNADIFFAREA 0.434700 ;
    PORT
      LAYER met2 ;
        RECT 217.210 319.240 217.490 319.520 ;
    END
  END dmem_axi_rdata_22
  PIN dmem_axi_rdata_23
    DIRECTION INPUT ;
    USE SIGNAL ;
    ANTENNAGATEAREA 0.647700 ;
    ANTENNADIFFAREA 0.434700 ;
    PORT
      LAYER met2 ;
        RECT 209.850 319.240 210.130 319.520 ;
    END
  END dmem_axi_rdata_23
  PIN dmem_axi_rdata_24
    DIRECTION INPUT ;
    USE SIGNAL ;
    ANTENNAGATEAREA 0.647700 ;
    ANTENNADIFFAREA 0.434700 ;
    PORT
      LAYER met2 ;
        RECT 238.370 319.240 238.650 319.520 ;
    END
  END dmem_axi_rdata_24
  PIN dmem_axi_rdata_25
    DIRECTION INPUT ;
    USE SIGNAL ;
    ANTENNAGATEAREA 0.647700 ;
    ANTENNADIFFAREA 0.434700 ;
    PORT
      LAYER met2 ;
        RECT 237.450 319.240 237.730 319.520 ;
    END
  END dmem_axi_rdata_25
  PIN dmem_axi_rdata_26
    DIRECTION INPUT ;
    USE SIGNAL ;
    ANTENNAGATEAREA 0.647700 ;
    ANTENNADIFFAREA 0.434700 ;
    PORT
      LAYER met2 ;
        RECT 231.930 319.240 232.210 319.520 ;
    END
  END dmem_axi_rdata_26
  PIN dmem_axi_rdata_27
    DIRECTION INPUT ;
    USE SIGNAL ;
    ANTENNAGATEAREA 0.647700 ;
    ANTENNADIFFAREA 0.434700 ;
    PORT
      LAYER met2 ;
        RECT 215.370 319.240 215.650 319.520 ;
    END
  END dmem_axi_rdata_27
  PIN dmem_axi_rdata_28
    DIRECTION INPUT ;
    USE SIGNAL ;
    ANTENNAGATEAREA 0.647700 ;
    ANTENNADIFFAREA 0.434700 ;
    PORT
      LAYER met2 ;
        RECT 213.530 319.240 213.810 319.520 ;
    END
  END dmem_axi_rdata_28
  PIN dmem_axi_rdata_29
    DIRECTION INPUT ;
    USE SIGNAL ;
    ANTENNAGATEAREA 0.647700 ;
    ANTENNADIFFAREA 0.434700 ;
    PORT
      LAYER met2 ;
        RECT 208.930 319.240 209.210 319.520 ;
    END
  END dmem_axi_rdata_29
  PIN dmem_axi_rdata_3
    DIRECTION INPUT ;
    USE SIGNAL ;
    ANTENNAGATEAREA 0.647700 ;
    ANTENNADIFFAREA 0.434700 ;
    PORT
      LAYER met3 ;
        RECT 308.200 291.080 308.800 291.680 ;
    END
  END dmem_axi_rdata_3
  PIN dmem_axi_rdata_30
    DIRECTION INPUT ;
    USE SIGNAL ;
    ANTENNAGATEAREA 0.647700 ;
    ANTENNADIFFAREA 0.434700 ;
    PORT
      LAYER met2 ;
        RECT 234.690 319.240 234.970 319.520 ;
    END
  END dmem_axi_rdata_30
  PIN dmem_axi_rdata_31
    DIRECTION INPUT ;
    USE SIGNAL ;
    ANTENNAGATEAREA 0.647700 ;
    ANTENNADIFFAREA 0.434700 ;
    PORT
      LAYER met2 ;
        RECT 221.810 319.240 222.090 319.520 ;
    END
  END dmem_axi_rdata_31
  PIN dmem_axi_rdata_4
    DIRECTION INPUT ;
    USE SIGNAL ;
    ANTENNAGATEAREA 0.647700 ;
    ANTENNADIFFAREA 0.434700 ;
    PORT
      LAYER met2 ;
        RECT 244.810 319.240 245.090 319.520 ;
    END
  END dmem_axi_rdata_4
  PIN dmem_axi_rdata_5
    DIRECTION INPUT ;
    USE SIGNAL ;
    ANTENNAGATEAREA 0.647700 ;
    ANTENNADIFFAREA 0.434700 ;
    PORT
      LAYER met3 ;
        RECT 308.200 179.560 308.800 180.160 ;
    END
  END dmem_axi_rdata_5
  PIN dmem_axi_rdata_6
    DIRECTION INPUT ;
    USE SIGNAL ;
    ANTENNAGATEAREA 0.647700 ;
    ANTENNADIFFAREA 0.434700 ;
    PORT
      LAYER met3 ;
        RECT 308.200 274.760 308.800 275.360 ;
    END
  END dmem_axi_rdata_6
  PIN dmem_axi_rdata_7
    DIRECTION INPUT ;
    USE SIGNAL ;
    ANTENNAGATEAREA 0.647700 ;
    ANTENNADIFFAREA 0.434700 ;
    PORT
      LAYER met3 ;
        RECT 308.200 277.480 308.800 278.080 ;
    END
  END dmem_axi_rdata_7
  PIN dmem_axi_rdata_8
    DIRECTION INPUT ;
    USE SIGNAL ;
    ANTENNAGATEAREA 0.647700 ;
    ANTENNADIFFAREA 0.434700 ;
    PORT
      LAYER met3 ;
        RECT 308.200 213.560 308.800 214.160 ;
    END
  END dmem_axi_rdata_8
  PIN dmem_axi_rdata_9
    DIRECTION INPUT ;
    USE SIGNAL ;
    ANTENNAGATEAREA 0.647700 ;
    ANTENNADIFFAREA 0.434700 ;
    PORT
      LAYER met3 ;
        RECT 308.200 189.080 308.800 189.680 ;
    END
  END dmem_axi_rdata_9
  PIN dmem_axi_rready
    DIRECTION OUTPUT ;
    USE SIGNAL ;
    ANTENNAGATEAREA 0.434700 ;
    ANTENNADIFFAREA 1.137600 ;
    PORT
      LAYER met3 ;
        RECT 308.200 172.760 308.800 173.360 ;
    END
  END dmem_axi_rready
  PIN dmem_axi_rresp_0
    DIRECTION INPUT ;
    USE SIGNAL ;
    PORT
      LAYER met2 ;
        RECT 3.770 0.000 4.050 0.280 ;
    END
  END dmem_axi_rresp_0
  PIN dmem_axi_rresp_1
    DIRECTION INPUT ;
    USE SIGNAL ;
    PORT
      LAYER met2 ;
        RECT 4.690 0.000 4.970 0.280 ;
    END
  END dmem_axi_rresp_1
  PIN dmem_axi_rvalid
    DIRECTION INPUT ;
    USE SIGNAL ;
    ANTENNAGATEAREA 0.647700 ;
    ANTENNADIFFAREA 0.434700 ;
    PORT
      LAYER met3 ;
        RECT 308.200 167.320 308.800 167.920 ;
    END
  END dmem_axi_rvalid
  PIN dmem_axi_wdata_0
    DIRECTION OUTPUT ;
    USE SIGNAL ;
    ANTENNAGATEAREA 0.434700 ;
    ANTENNADIFFAREA 1.137600 ;
    PORT
      LAYER met2 ;
        RECT 236.530 0.000 236.810 0.280 ;
    END
  END dmem_axi_wdata_0
  PIN dmem_axi_wdata_1
    DIRECTION OUTPUT ;
    USE SIGNAL ;
    ANTENNAGATEAREA 0.434700 ;
    ANTENNADIFFAREA 1.137600 ;
    PORT
      LAYER met2 ;
        RECT 252.170 0.000 252.450 0.280 ;
    END
  END dmem_axi_wdata_1
  PIN dmem_axi_wdata_10
    DIRECTION OUTPUT ;
    USE SIGNAL ;
    ANTENNAGATEAREA 0.434700 ;
    ANTENNADIFFAREA 1.137600 ;
    PORT
      LAYER met2 ;
        RECT 246.650 0.000 246.930 0.280 ;
    END
  END dmem_axi_wdata_10
  PIN dmem_axi_wdata_11
    DIRECTION OUTPUT ;
    USE SIGNAL ;
    ANTENNAGATEAREA 0.434700 ;
    ANTENNADIFFAREA 1.137600 ;
    PORT
      LAYER met2 ;
        RECT 248.490 0.000 248.770 0.280 ;
    END
  END dmem_axi_wdata_11
  PIN dmem_axi_wdata_12
    DIRECTION OUTPUT ;
    USE SIGNAL ;
    ANTENNAGATEAREA 0.434700 ;
    ANTENNADIFFAREA 1.137600 ;
    PORT
      LAYER met3 ;
        RECT 308.200 99.320 308.800 99.920 ;
    END
  END dmem_axi_wdata_12
  PIN dmem_axi_wdata_13
    DIRECTION OUTPUT ;
    USE SIGNAL ;
    ANTENNAGATEAREA 0.434700 ;
    ANTENNADIFFAREA 1.137600 ;
    PORT
      LAYER met3 ;
        RECT 308.200 134.680 308.800 135.280 ;
    END
  END dmem_axi_wdata_13
  PIN dmem_axi_wdata_14
    DIRECTION OUTPUT ;
    USE SIGNAL ;
    ANTENNAGATEAREA 0.434700 ;
    ANTENNADIFFAREA 1.137600 ;
    PORT
      LAYER met2 ;
        RECT 277.930 0.000 278.210 0.280 ;
    END
  END dmem_axi_wdata_14
  PIN dmem_axi_wdata_15
    DIRECTION OUTPUT ;
    USE SIGNAL ;
    ANTENNAGATEAREA 0.434700 ;
    ANTENNADIFFAREA 1.137600 ;
    PORT
      LAYER met3 ;
        RECT 308.200 92.520 308.800 93.120 ;
    END
  END dmem_axi_wdata_15
  PIN dmem_axi_wdata_16
    DIRECTION OUTPUT ;
    USE SIGNAL ;
    ANTENNAGATEAREA 0.434700 ;
    ANTENNADIFFAREA 1.137600 ;
    PORT
      LAYER met3 ;
        RECT 308.200 78.920 308.800 79.520 ;
    END
  END dmem_axi_wdata_16
  PIN dmem_axi_wdata_17
    DIRECTION OUTPUT ;
    USE SIGNAL ;
    ANTENNAGATEAREA 0.434700 ;
    ANTENNADIFFAREA 1.137600 ;
    PORT
      LAYER met3 ;
        RECT 308.200 151.000 308.800 151.600 ;
    END
  END dmem_axi_wdata_17
  PIN dmem_axi_wdata_18
    DIRECTION OUTPUT ;
    USE SIGNAL ;
    ANTENNAGATEAREA 0.434700 ;
    ANTENNADIFFAREA 1.137600 ;
    PORT
      LAYER met2 ;
        RECT 253.090 0.000 253.370 0.280 ;
    END
  END dmem_axi_wdata_18
  PIN dmem_axi_wdata_19
    DIRECTION OUTPUT ;
    USE SIGNAL ;
    ANTENNAGATEAREA 0.434700 ;
    ANTENNADIFFAREA 1.137600 ;
    PORT
      LAYER met2 ;
        RECT 216.290 0.000 216.570 0.280 ;
    END
  END dmem_axi_wdata_19
  PIN dmem_axi_wdata_2
    DIRECTION OUTPUT ;
    USE SIGNAL ;
    ANTENNAGATEAREA 0.434700 ;
    ANTENNADIFFAREA 1.137600 ;
    PORT
      LAYER met3 ;
        RECT 308.200 100.680 308.800 101.280 ;
    END
  END dmem_axi_wdata_2
  PIN dmem_axi_wdata_20
    DIRECTION OUTPUT ;
    USE SIGNAL ;
    ANTENNAGATEAREA 0.434700 ;
    ANTENNADIFFAREA 1.137600 ;
    PORT
      LAYER met3 ;
        RECT 308.200 115.640 308.800 116.240 ;
    END
  END dmem_axi_wdata_20
  PIN dmem_axi_wdata_21
    DIRECTION OUTPUT ;
    USE SIGNAL ;
    ANTENNAGATEAREA 0.434700 ;
    ANTENNADIFFAREA 1.137600 ;
    PORT
      LAYER met2 ;
        RECT 209.850 0.000 210.130 0.280 ;
    END
  END dmem_axi_wdata_21
  PIN dmem_axi_wdata_22
    DIRECTION OUTPUT ;
    USE SIGNAL ;
    ANTENNAGATEAREA 0.434700 ;
    ANTENNADIFFAREA 1.137600 ;
    PORT
      LAYER met2 ;
        RECT 221.810 0.000 222.090 0.280 ;
    END
  END dmem_axi_wdata_22
  PIN dmem_axi_wdata_23
    DIRECTION OUTPUT ;
    USE SIGNAL ;
    ANTENNAGATEAREA 0.434700 ;
    ANTENNADIFFAREA 1.137600 ;
    PORT
      LAYER met2 ;
        RECT 277.010 0.000 277.290 0.280 ;
    END
  END dmem_axi_wdata_23
  PIN dmem_axi_wdata_24
    DIRECTION OUTPUT ;
    USE SIGNAL ;
    ANTENNAGATEAREA 0.434700 ;
    ANTENNADIFFAREA 1.137600 ;
    PORT
      LAYER met3 ;
        RECT 308.200 149.640 308.800 150.240 ;
    END
  END dmem_axi_wdata_24
  PIN dmem_axi_wdata_25
    DIRECTION OUTPUT ;
    USE SIGNAL ;
    ANTENNAGATEAREA 0.434700 ;
    ANTENNADIFFAREA 1.137600 ;
    PORT
      LAYER met2 ;
        RECT 213.530 0.000 213.810 0.280 ;
    END
  END dmem_axi_wdata_25
  PIN dmem_axi_wdata_26
    DIRECTION OUTPUT ;
    USE SIGNAL ;
    ANTENNAGATEAREA 0.434700 ;
    ANTENNADIFFAREA 1.137600 ;
    PORT
      LAYER met2 ;
        RECT 269.650 0.000 269.930 0.280 ;
    END
  END dmem_axi_wdata_26
  PIN dmem_axi_wdata_27
    DIRECTION OUTPUT ;
    USE SIGNAL ;
    ANTENNAGATEAREA 0.434700 ;
    ANTENNADIFFAREA 1.137600 ;
    PORT
      LAYER met3 ;
        RECT 308.200 114.280 308.800 114.880 ;
    END
  END dmem_axi_wdata_27
  PIN dmem_axi_wdata_28
    DIRECTION OUTPUT ;
    USE SIGNAL ;
    ANTENNAGATEAREA 0.434700 ;
    ANTENNADIFFAREA 1.137600 ;
    PORT
      LAYER met3 ;
        RECT 308.200 72.120 308.800 72.720 ;
    END
  END dmem_axi_wdata_28
  PIN dmem_axi_wdata_29
    DIRECTION OUTPUT ;
    USE SIGNAL ;
    ANTENNAGATEAREA 0.434700 ;
    ANTENNADIFFAREA 1.137600 ;
    PORT
      LAYER met2 ;
        RECT 212.610 0.000 212.890 0.280 ;
    END
  END dmem_axi_wdata_29
  PIN dmem_axi_wdata_3
    DIRECTION OUTPUT ;
    USE SIGNAL ;
    ANTENNAGATEAREA 0.434700 ;
    ANTENNADIFFAREA 1.137600 ;
    PORT
      LAYER met2 ;
        RECT 232.850 0.000 233.130 0.280 ;
    END
  END dmem_axi_wdata_3
  PIN dmem_axi_wdata_30
    DIRECTION OUTPUT ;
    USE SIGNAL ;
    ANTENNAGATEAREA 0.434700 ;
    ANTENNADIFFAREA 1.137600 ;
    PORT
      LAYER met3 ;
        RECT 308.200 112.920 308.800 113.520 ;
    END
  END dmem_axi_wdata_30
  PIN dmem_axi_wdata_31
    DIRECTION OUTPUT ;
    USE SIGNAL ;
    ANTENNAGATEAREA 0.434700 ;
    ANTENNADIFFAREA 1.137600 ;
    PORT
      LAYER met3 ;
        RECT 308.200 106.120 308.800 106.720 ;
    END
  END dmem_axi_wdata_31
  PIN dmem_axi_wdata_4
    DIRECTION OUTPUT ;
    USE SIGNAL ;
    ANTENNAGATEAREA 0.434700 ;
    ANTENNADIFFAREA 1.137600 ;
    PORT
      LAYER met2 ;
        RECT 220.890 0.000 221.170 0.280 ;
    END
  END dmem_axi_wdata_4
  PIN dmem_axi_wdata_5
    DIRECTION OUTPUT ;
    USE SIGNAL ;
    ANTENNAGATEAREA 0.434700 ;
    ANTENNADIFFAREA 1.137600 ;
    PORT
      LAYER met3 ;
        RECT 308.200 142.840 308.800 143.440 ;
    END
  END dmem_axi_wdata_5
  PIN dmem_axi_wdata_6
    DIRECTION OUTPUT ;
    USE SIGNAL ;
    ANTENNAGATEAREA 0.434700 ;
    ANTENNADIFFAREA 1.137600 ;
    PORT
      LAYER met3 ;
        RECT 308.200 95.240 308.800 95.840 ;
    END
  END dmem_axi_wdata_6
  PIN dmem_axi_wdata_7
    DIRECTION OUTPUT ;
    USE SIGNAL ;
    ANTENNAGATEAREA 0.434700 ;
    ANTENNADIFFAREA 1.137600 ;
    PORT
      LAYER met2 ;
        RECT 219.970 0.000 220.250 0.280 ;
    END
  END dmem_axi_wdata_7
  PIN dmem_axi_wdata_8
    DIRECTION OUTPUT ;
    USE SIGNAL ;
    ANTENNAGATEAREA 0.434700 ;
    ANTENNADIFFAREA 1.137600 ;
    PORT
      LAYER met3 ;
        RECT 308.200 137.400 308.800 138.000 ;
    END
  END dmem_axi_wdata_8
  PIN dmem_axi_wdata_9
    DIRECTION OUTPUT ;
    USE SIGNAL ;
    ANTENNAGATEAREA 0.434700 ;
    ANTENNADIFFAREA 1.137600 ;
    PORT
      LAYER met3 ;
        RECT 308.200 102.040 308.800 102.640 ;
    END
  END dmem_axi_wdata_9
  PIN dmem_axi_wready
    DIRECTION INPUT ;
    USE SIGNAL ;
    ANTENNAGATEAREA 0.647700 ;
    ANTENNADIFFAREA 0.434700 ;
    PORT
      LAYER met3 ;
        RECT 308.200 146.920 308.800 147.520 ;
    END
  END dmem_axi_wready
  PIN dmem_axi_wstrb_0
    DIRECTION OUTPUT ;
    USE SIGNAL ;
    ANTENNAGATEAREA 0.434700 ;
    ANTENNADIFFAREA 1.137600 ;
    PORT
      LAYER met3 ;
        RECT 308.200 118.360 308.800 118.960 ;
    END
  END dmem_axi_wstrb_0
  PIN dmem_axi_wstrb_1
    DIRECTION OUTPUT ;
    USE SIGNAL ;
    ANTENNAGATEAREA 0.434700 ;
    ANTENNADIFFAREA 1.137600 ;
    PORT
      LAYER met3 ;
        RECT 308.200 121.080 308.800 121.680 ;
    END
  END dmem_axi_wstrb_1
  PIN dmem_axi_wstrb_2
    DIRECTION OUTPUT ;
    USE SIGNAL ;
    ANTENNAGATEAREA 0.434700 ;
    ANTENNADIFFAREA 1.137600 ;
    PORT
      LAYER met3 ;
        RECT 308.200 122.440 308.800 123.040 ;
    END
  END dmem_axi_wstrb_2
  PIN dmem_axi_wstrb_3
    DIRECTION OUTPUT ;
    USE SIGNAL ;
    ANTENNAGATEAREA 0.434700 ;
    ANTENNADIFFAREA 1.137600 ;
    PORT
      LAYER met3 ;
        RECT 308.200 119.720 308.800 120.320 ;
    END
  END dmem_axi_wstrb_3
  PIN dmem_axi_wvalid
    DIRECTION OUTPUT ;
    USE SIGNAL ;
    ANTENNAGATEAREA 0.434700 ;
    ANTENNADIFFAREA 1.137600 ;
    PORT
      LAYER met3 ;
        RECT 308.200 145.560 308.800 146.160 ;
    END
  END dmem_axi_wvalid
  PIN dmem_rdata_0
    DIRECTION OUTPUT ;
    USE SIGNAL ;
    ANTENNAGATEAREA 0.434700 ;
    ANTENNADIFFAREA 1.137600 ;
    PORT
      LAYER met3 ;
        RECT 308.200 182.280 308.800 182.880 ;
    END
  END dmem_rdata_0
  PIN dmem_rdata_1
    DIRECTION OUTPUT ;
    USE SIGNAL ;
    ANTENNAGATEAREA 0.434700 ;
    ANTENNADIFFAREA 1.137600 ;
    PORT
      LAYER met3 ;
        RECT 308.200 174.120 308.800 174.720 ;
    END
  END dmem_rdata_1
  PIN dmem_rdata_10
    DIRECTION OUTPUT ;
    USE SIGNAL ;
    ANTENNAGATEAREA 0.434700 ;
    ANTENNADIFFAREA 1.137600 ;
    PORT
      LAYER met3 ;
        RECT 308.200 292.440 308.800 293.040 ;
    END
  END dmem_rdata_10
  PIN dmem_rdata_11
    DIRECTION OUTPUT ;
    USE SIGNAL ;
    ANTENNAGATEAREA 0.434700 ;
    ANTENNADIFFAREA 1.137600 ;
    PORT
      LAYER met2 ;
        RECT 249.410 319.240 249.690 319.520 ;
    END
  END dmem_rdata_11
  PIN dmem_rdata_12
    DIRECTION OUTPUT ;
    USE SIGNAL ;
    ANTENNAGATEAREA 0.434700 ;
    ANTENNADIFFAREA 1.137600 ;
    PORT
      LAYER met3 ;
        RECT 308.200 282.920 308.800 283.520 ;
    END
  END dmem_rdata_12
  PIN dmem_rdata_13
    DIRECTION OUTPUT ;
    USE SIGNAL ;
    ANTENNAGATEAREA 0.434700 ;
    ANTENNADIFFAREA 1.137600 ;
    PORT
      LAYER met3 ;
        RECT 308.200 280.200 308.800 280.800 ;
    END
  END dmem_rdata_13
  PIN dmem_rdata_14
    DIRECTION OUTPUT ;
    USE SIGNAL ;
    ANTENNAGATEAREA 0.434700 ;
    ANTENNADIFFAREA 1.137600 ;
    PORT
      LAYER met3 ;
        RECT 308.200 288.360 308.800 288.960 ;
    END
  END dmem_rdata_14
  PIN dmem_rdata_15
    DIRECTION OUTPUT ;
    USE SIGNAL ;
    ANTENNAGATEAREA 0.434700 ;
    ANTENNADIFFAREA 1.137600 ;
    PORT
      LAYER met3 ;
        RECT 308.200 273.400 308.800 274.000 ;
    END
  END dmem_rdata_15
  PIN dmem_rdata_16
    DIRECTION OUTPUT ;
    USE SIGNAL ;
    ANTENNAGATEAREA 0.434700 ;
    ANTENNADIFFAREA 1.137600 ;
    PORT
      LAYER met3 ;
        RECT 308.200 171.400 308.800 172.000 ;
    END
  END dmem_rdata_16
  PIN dmem_rdata_17
    DIRECTION OUTPUT ;
    USE SIGNAL ;
    ANTENNAGATEAREA 0.434700 ;
    ANTENNADIFFAREA 1.137600 ;
    PORT
      LAYER met3 ;
        RECT 308.200 168.680 308.800 169.280 ;
    END
  END dmem_rdata_17
  PIN dmem_rdata_18
    DIRECTION OUTPUT ;
    USE SIGNAL ;
    ANTENNAGATEAREA 0.434700 ;
    ANTENNADIFFAREA 1.137600 ;
    PORT
      LAYER met3 ;
        RECT 308.200 183.640 308.800 184.240 ;
    END
  END dmem_rdata_18
  PIN dmem_rdata_19
    DIRECTION OUTPUT ;
    USE SIGNAL ;
    ANTENNAGATEAREA 0.434700 ;
    ANTENNADIFFAREA 1.137600 ;
    PORT
      LAYER met3 ;
        RECT 308.200 176.840 308.800 177.440 ;
    END
  END dmem_rdata_19
  PIN dmem_rdata_2
    DIRECTION OUTPUT ;
    USE SIGNAL ;
    ANTENNAGATEAREA 0.434700 ;
    ANTENNADIFFAREA 1.137600 ;
    PORT
      LAYER met3 ;
        RECT 308.200 204.040 308.800 204.640 ;
    END
  END dmem_rdata_2
  PIN dmem_rdata_20
    DIRECTION OUTPUT ;
    USE SIGNAL ;
    ANTENNAGATEAREA 0.434700 ;
    ANTENNADIFFAREA 1.137600 ;
    PORT
      LAYER met2 ;
        RECT 218.130 319.240 218.410 319.520 ;
    END
  END dmem_rdata_20
  PIN dmem_rdata_21
    DIRECTION OUTPUT ;
    USE SIGNAL ;
    ANTENNAGATEAREA 0.434700 ;
    ANTENNADIFFAREA 1.137600 ;
    PORT
      LAYER met2 ;
        RECT 219.050 319.240 219.330 319.520 ;
    END
  END dmem_rdata_21
  PIN dmem_rdata_22
    DIRECTION OUTPUT ;
    USE SIGNAL ;
    ANTENNAGATEAREA 0.434700 ;
    ANTENNADIFFAREA 1.137600 ;
    PORT
      LAYER met2 ;
        RECT 220.890 319.240 221.170 319.520 ;
    END
  END dmem_rdata_22
  PIN dmem_rdata_23
    DIRECTION OUTPUT ;
    USE SIGNAL ;
    ANTENNAGATEAREA 0.434700 ;
    ANTENNADIFFAREA 1.137600 ;
    PORT
      LAYER met2 ;
        RECT 210.770 319.240 211.050 319.520 ;
    END
  END dmem_rdata_23
  PIN dmem_rdata_24
    DIRECTION OUTPUT ;
    USE SIGNAL ;
    ANTENNAGATEAREA 0.434700 ;
    ANTENNADIFFAREA 1.137600 ;
    PORT
      LAYER met2 ;
        RECT 243.890 319.240 244.170 319.520 ;
    END
  END dmem_rdata_24
  PIN dmem_rdata_25
    DIRECTION OUTPUT ;
    USE SIGNAL ;
    ANTENNAGATEAREA 0.434700 ;
    ANTENNADIFFAREA 1.137600 ;
    PORT
      LAYER met2 ;
        RECT 242.050 319.240 242.330 319.520 ;
    END
  END dmem_rdata_25
  PIN dmem_rdata_26
    DIRECTION OUTPUT ;
    USE SIGNAL ;
    ANTENNAGATEAREA 0.434700 ;
    ANTENNADIFFAREA 1.137600 ;
    PORT
      LAYER met2 ;
        RECT 233.770 319.240 234.050 319.520 ;
    END
  END dmem_rdata_26
  PIN dmem_rdata_27
    DIRECTION OUTPUT ;
    USE SIGNAL ;
    ANTENNAGATEAREA 0.434700 ;
    ANTENNADIFFAREA 1.137600 ;
    PORT
      LAYER met2 ;
        RECT 212.610 319.240 212.890 319.520 ;
    END
  END dmem_rdata_27
  PIN dmem_rdata_28
    DIRECTION OUTPUT ;
    USE SIGNAL ;
    ANTENNAGATEAREA 0.434700 ;
    ANTENNADIFFAREA 1.137600 ;
    PORT
      LAYER met2 ;
        RECT 214.450 319.240 214.730 319.520 ;
    END
  END dmem_rdata_28
  PIN dmem_rdata_29
    DIRECTION OUTPUT ;
    USE SIGNAL ;
    ANTENNAGATEAREA 0.434700 ;
    ANTENNADIFFAREA 1.137600 ;
    PORT
      LAYER met2 ;
        RECT 208.010 319.240 208.290 319.520 ;
    END
  END dmem_rdata_29
  PIN dmem_rdata_3
    DIRECTION OUTPUT ;
    USE SIGNAL ;
    ANTENNAGATEAREA 0.434700 ;
    ANTENNADIFFAREA 1.137600 ;
    PORT
      LAYER met3 ;
        RECT 308.200 281.560 308.800 282.160 ;
    END
  END dmem_rdata_3
  PIN dmem_rdata_30
    DIRECTION OUTPUT ;
    USE SIGNAL ;
    ANTENNAGATEAREA 0.434700 ;
    ANTENNADIFFAREA 1.137600 ;
    PORT
      LAYER met2 ;
        RECT 236.530 319.240 236.810 319.520 ;
    END
  END dmem_rdata_30
  PIN dmem_rdata_31
    DIRECTION OUTPUT ;
    USE SIGNAL ;
    ANTENNAGATEAREA 0.434700 ;
    ANTENNADIFFAREA 1.137600 ;
    PORT
      LAYER met2 ;
        RECT 223.650 319.240 223.930 319.520 ;
    END
  END dmem_rdata_31
  PIN dmem_rdata_4
    DIRECTION OUTPUT ;
    USE SIGNAL ;
    ANTENNAGATEAREA 0.434700 ;
    ANTENNADIFFAREA 1.137600 ;
    PORT
      LAYER met3 ;
        RECT 308.200 210.840 308.800 211.440 ;
    END
  END dmem_rdata_4
  PIN dmem_rdata_5
    DIRECTION OUTPUT ;
    USE SIGNAL ;
    ANTENNAGATEAREA 0.434700 ;
    ANTENNADIFFAREA 1.137600 ;
    PORT
      LAYER met3 ;
        RECT 308.200 180.920 308.800 181.520 ;
    END
  END dmem_rdata_5
  PIN dmem_rdata_6
    DIRECTION OUTPUT ;
    USE SIGNAL ;
    ANTENNAGATEAREA 0.434700 ;
    ANTENNADIFFAREA 1.137600 ;
    PORT
      LAYER met3 ;
        RECT 308.200 276.120 308.800 276.720 ;
    END
  END dmem_rdata_6
  PIN dmem_rdata_7
    DIRECTION OUTPUT ;
    USE SIGNAL ;
    ANTENNAGATEAREA 0.434700 ;
    ANTENNADIFFAREA 1.137600 ;
    PORT
      LAYER met3 ;
        RECT 308.200 289.720 308.800 290.320 ;
    END
  END dmem_rdata_7
  PIN dmem_rdata_8
    DIRECTION OUTPUT ;
    USE SIGNAL ;
    ANTENNAGATEAREA 0.434700 ;
    ANTENNADIFFAREA 1.137600 ;
    PORT
      LAYER met3 ;
        RECT 308.200 214.920 308.800 215.520 ;
    END
  END dmem_rdata_8
  PIN dmem_rdata_9
    DIRECTION OUTPUT ;
    USE SIGNAL ;
    ANTENNAGATEAREA 0.434700 ;
    ANTENNADIFFAREA 1.137600 ;
    PORT
      LAYER met3 ;
        RECT 308.200 187.720 308.800 188.320 ;
    END
  END dmem_rdata_9
  PIN dmem_ready
    DIRECTION OUTPUT ;
    USE SIGNAL ;
    ANTENNAGATEAREA 0.434700 ;
    ANTENNADIFFAREA 1.137600 ;
    PORT
      LAYER met2 ;
        RECT 211.690 319.240 211.970 319.520 ;
    END
  END dmem_ready
  PIN dmem_req
    DIRECTION INPUT ;
    USE SIGNAL ;
    ANTENNAGATEAREA 0.647700 ;
    ANTENNADIFFAREA 0.434700 ;
    PORT
      LAYER met3 ;
        RECT 308.200 156.440 308.800 157.040 ;
    END
  END dmem_req
  PIN dmem_wdata_0
    DIRECTION INPUT ;
    USE SIGNAL ;
    ANTENNAGATEAREA 0.647700 ;
    ANTENNADIFFAREA 0.434700 ;
    PORT
      LAYER met2 ;
        RECT 235.610 0.000 235.890 0.280 ;
    END
  END dmem_wdata_0
  PIN dmem_wdata_1
    DIRECTION INPUT ;
    USE SIGNAL ;
    ANTENNAGATEAREA 0.647700 ;
    ANTENNADIFFAREA 0.434700 ;
    PORT
      LAYER met2 ;
        RECT 250.330 0.000 250.610 0.280 ;
    END
  END dmem_wdata_1
  PIN dmem_wdata_10
    DIRECTION INPUT ;
    USE SIGNAL ;
    ANTENNAGATEAREA 0.647700 ;
    ANTENNADIFFAREA 0.434700 ;
    PORT
      LAYER met2 ;
        RECT 247.570 0.000 247.850 0.280 ;
    END
  END dmem_wdata_10
  PIN dmem_wdata_11
    DIRECTION INPUT ;
    USE SIGNAL ;
    ANTENNAGATEAREA 0.647700 ;
    ANTENNADIFFAREA 0.434700 ;
    PORT
      LAYER met2 ;
        RECT 249.410 0.000 249.690 0.280 ;
    END
  END dmem_wdata_11
  PIN dmem_wdata_12
    DIRECTION INPUT ;
    USE SIGNAL ;
    ANTENNAGATEAREA 0.647700 ;
    ANTENNADIFFAREA 0.434700 ;
    PORT
      LAYER met3 ;
        RECT 308.200 107.480 308.800 108.080 ;
    END
  END dmem_wdata_12
  PIN dmem_wdata_13
    DIRECTION INPUT ;
    USE SIGNAL ;
    ANTENNAGATEAREA 0.647700 ;
    ANTENNADIFFAREA 0.434700 ;
    PORT
      LAYER met3 ;
        RECT 308.200 133.320 308.800 133.920 ;
    END
  END dmem_wdata_13
  PIN dmem_wdata_14
    DIRECTION INPUT ;
    USE SIGNAL ;
    ANTENNAGATEAREA 0.647700 ;
    ANTENNADIFFAREA 0.434700 ;
    PORT
      LAYER met2 ;
        RECT 276.090 0.000 276.370 0.280 ;
    END
  END dmem_wdata_14
  PIN dmem_wdata_15
    DIRECTION INPUT ;
    USE SIGNAL ;
    ANTENNAGATEAREA 0.647700 ;
    ANTENNADIFFAREA 0.434700 ;
    PORT
      LAYER met3 ;
        RECT 308.200 91.160 308.800 91.760 ;
    END
  END dmem_wdata_15
  PIN dmem_wdata_16
    DIRECTION INPUT ;
    USE SIGNAL ;
    ANTENNAGATEAREA 0.647700 ;
    ANTENNADIFFAREA 0.434700 ;
    PORT
      LAYER met3 ;
        RECT 308.200 77.560 308.800 78.160 ;
    END
  END dmem_wdata_16
  PIN dmem_wdata_17
    DIRECTION INPUT ;
    USE SIGNAL ;
    ANTENNAGATEAREA 0.647700 ;
    ANTENNADIFFAREA 0.434700 ;
    PORT
      LAYER met3 ;
        RECT 308.200 141.480 308.800 142.080 ;
    END
  END dmem_wdata_17
  PIN dmem_wdata_18
    DIRECTION INPUT ;
    USE SIGNAL ;
    ANTENNAGATEAREA 0.647700 ;
    ANTENNADIFFAREA 0.434700 ;
    PORT
      LAYER met2 ;
        RECT 251.250 0.000 251.530 0.280 ;
    END
  END dmem_wdata_18
  PIN dmem_wdata_19
    DIRECTION INPUT ;
    USE SIGNAL ;
    ANTENNAGATEAREA 0.647700 ;
    ANTENNADIFFAREA 0.434700 ;
    PORT
      LAYER met2 ;
        RECT 215.370 0.000 215.650 0.280 ;
    END
  END dmem_wdata_19
  PIN dmem_wdata_2
    DIRECTION INPUT ;
    USE SIGNAL ;
    ANTENNAGATEAREA 0.647700 ;
    ANTENNADIFFAREA 0.434700 ;
    PORT
      LAYER met3 ;
        RECT 308.200 103.400 308.800 104.000 ;
    END
  END dmem_wdata_2
  PIN dmem_wdata_20
    DIRECTION INPUT ;
    USE SIGNAL ;
    ANTENNAGATEAREA 0.647700 ;
    ANTENNADIFFAREA 0.434700 ;
    PORT
      LAYER met3 ;
        RECT 308.200 117.000 308.800 117.600 ;
    END
  END dmem_wdata_20
  PIN dmem_wdata_21
    DIRECTION INPUT ;
    USE SIGNAL ;
    ANTENNAGATEAREA 0.647700 ;
    ANTENNADIFFAREA 0.434700 ;
    PORT
      LAYER met2 ;
        RECT 210.770 0.000 211.050 0.280 ;
    END
  END dmem_wdata_21
  PIN dmem_wdata_22
    DIRECTION INPUT ;
    USE SIGNAL ;
    ANTENNAGATEAREA 0.647700 ;
    ANTENNADIFFAREA 0.434700 ;
    PORT
      LAYER met2 ;
        RECT 218.130 0.000 218.410 0.280 ;
    END
  END dmem_wdata_22
  PIN dmem_wdata_23
    DIRECTION INPUT ;
    USE SIGNAL ;
    ANTENNAGATEAREA 0.647700 ;
    ANTENNADIFFAREA 0.434700 ;
    PORT
      LAYER met2 ;
        RECT 275.170 0.000 275.450 0.280 ;
    END
  END dmem_wdata_23
  PIN dmem_wdata_24
    DIRECTION INPUT ;
    USE SIGNAL ;
    ANTENNAGATEAREA 0.647700 ;
    ANTENNADIFFAREA 0.434700 ;
    PORT
      LAYER met3 ;
        RECT 308.200 144.200 308.800 144.800 ;
    END
  END dmem_wdata_24
  PIN dmem_wdata_25
    DIRECTION INPUT ;
    USE SIGNAL ;
    ANTENNAGATEAREA 0.647700 ;
    ANTENNADIFFAREA 0.434700 ;
    PORT
      LAYER met2 ;
        RECT 214.450 0.000 214.730 0.280 ;
    END
  END dmem_wdata_25
  PIN dmem_wdata_26
    DIRECTION INPUT ;
    USE SIGNAL ;
    ANTENNAGATEAREA 0.647700 ;
    ANTENNADIFFAREA 0.434700 ;
    PORT
      LAYER met2 ;
        RECT 270.570 0.000 270.850 0.280 ;
    END
  END dmem_wdata_26
  PIN dmem_wdata_27
    DIRECTION INPUT ;
    USE SIGNAL ;
    ANTENNAGATEAREA 0.647700 ;
    ANTENNADIFFAREA 0.434700 ;
    PORT
      LAYER met3 ;
        RECT 308.200 108.840 308.800 109.440 ;
    END
  END dmem_wdata_27
  PIN dmem_wdata_28
    DIRECTION INPUT ;
    USE SIGNAL ;
    ANTENNAGATEAREA 0.647700 ;
    ANTENNADIFFAREA 0.434700 ;
    PORT
      LAYER met3 ;
        RECT 308.200 70.760 308.800 71.360 ;
    END
  END dmem_wdata_28
  PIN dmem_wdata_29
    DIRECTION INPUT ;
    USE SIGNAL ;
    ANTENNAGATEAREA 0.647700 ;
    ANTENNADIFFAREA 0.434700 ;
    PORT
      LAYER met2 ;
        RECT 211.690 0.000 211.970 0.280 ;
    END
  END dmem_wdata_29
  PIN dmem_wdata_3
    DIRECTION INPUT ;
    USE SIGNAL ;
    ANTENNAGATEAREA 0.647700 ;
    ANTENNADIFFAREA 0.434700 ;
    PORT
      LAYER met2 ;
        RECT 233.770 0.000 234.050 0.280 ;
    END
  END dmem_wdata_3
  PIN dmem_wdata_30
    DIRECTION INPUT ;
    USE SIGNAL ;
    ANTENNAGATEAREA 0.647700 ;
    ANTENNADIFFAREA 0.434700 ;
    PORT
      LAYER met3 ;
        RECT 308.200 111.560 308.800 112.160 ;
    END
  END dmem_wdata_30
  PIN dmem_wdata_31
    DIRECTION INPUT ;
    USE SIGNAL ;
    ANTENNAGATEAREA 0.647700 ;
    ANTENNADIFFAREA 0.434700 ;
    PORT
      LAYER met3 ;
        RECT 308.200 110.200 308.800 110.800 ;
    END
  END dmem_wdata_31
  PIN dmem_wdata_4
    DIRECTION INPUT ;
    USE SIGNAL ;
    ANTENNAGATEAREA 0.647700 ;
    ANTENNADIFFAREA 0.434700 ;
    PORT
      LAYER met2 ;
        RECT 219.050 0.000 219.330 0.280 ;
    END
  END dmem_wdata_4
  PIN dmem_wdata_5
    DIRECTION INPUT ;
    USE SIGNAL ;
    ANTENNAGATEAREA 0.647700 ;
    ANTENNADIFFAREA 0.434700 ;
    PORT
      LAYER met3 ;
        RECT 308.200 148.280 308.800 148.880 ;
    END
  END dmem_wdata_5
  PIN dmem_wdata_6
    DIRECTION INPUT ;
    USE SIGNAL ;
    ANTENNAGATEAREA 0.647700 ;
    ANTENNADIFFAREA 0.434700 ;
    PORT
      LAYER met3 ;
        RECT 308.200 93.880 308.800 94.480 ;
    END
  END dmem_wdata_6
  PIN dmem_wdata_7
    DIRECTION INPUT ;
    USE SIGNAL ;
    ANTENNAGATEAREA 0.647700 ;
    ANTENNADIFFAREA 0.434700 ;
    PORT
      LAYER met2 ;
        RECT 217.210 0.000 217.490 0.280 ;
    END
  END dmem_wdata_7
  PIN dmem_wdata_8
    DIRECTION INPUT ;
    USE SIGNAL ;
    ANTENNAGATEAREA 0.647700 ;
    ANTENNADIFFAREA 0.434700 ;
    PORT
      LAYER met3 ;
        RECT 308.200 136.040 308.800 136.640 ;
    END
  END dmem_wdata_8
  PIN dmem_wdata_9
    DIRECTION INPUT ;
    USE SIGNAL ;
    ANTENNAGATEAREA 0.647700 ;
    ANTENNADIFFAREA 0.434700 ;
    PORT
      LAYER met3 ;
        RECT 308.200 104.760 308.800 105.360 ;
    END
  END dmem_wdata_9
  PIN dmem_wstrb_0
    DIRECTION INPUT ;
    USE SIGNAL ;
    ANTENNAGATEAREA 0.647700 ;
    ANTENNADIFFAREA 0.434700 ;
    PORT
      LAYER met3 ;
        RECT 308.200 127.880 308.800 128.480 ;
    END
  END dmem_wstrb_0
  PIN dmem_wstrb_1
    DIRECTION INPUT ;
    USE SIGNAL ;
    ANTENNAGATEAREA 0.647700 ;
    ANTENNADIFFAREA 0.434700 ;
    PORT
      LAYER met3 ;
        RECT 308.200 125.160 308.800 125.760 ;
    END
  END dmem_wstrb_1
  PIN dmem_wstrb_2
    DIRECTION INPUT ;
    USE SIGNAL ;
    ANTENNAGATEAREA 0.647700 ;
    ANTENNADIFFAREA 0.434700 ;
    PORT
      LAYER met3 ;
        RECT 308.200 123.800 308.800 124.400 ;
    END
  END dmem_wstrb_2
  PIN dmem_wstrb_3
    DIRECTION INPUT ;
    USE SIGNAL ;
    ANTENNAGATEAREA 0.647700 ;
    ANTENNADIFFAREA 0.434700 ;
    PORT
      LAYER met3 ;
        RECT 308.200 126.520 308.800 127.120 ;
    END
  END dmem_wstrb_3
  PIN imem_addr_0
    DIRECTION INPUT ;
    USE SIGNAL ;
    ANTENNAGATEAREA 0.647700 ;
    ANTENNADIFFAREA 0.434700 ;
    PORT
      LAYER met2 ;
        RECT 73.690 319.240 73.970 319.520 ;
    END
  END imem_addr_0
  PIN imem_addr_1
    DIRECTION INPUT ;
    USE SIGNAL ;
    ANTENNAGATEAREA 0.647700 ;
    ANTENNADIFFAREA 0.434700 ;
    PORT
      LAYER met2 ;
        RECT 38.730 319.240 39.010 319.520 ;
    END
  END imem_addr_1
  PIN imem_addr_10
    DIRECTION INPUT ;
    USE SIGNAL ;
    ANTENNAGATEAREA 0.647700 ;
    ANTENNADIFFAREA 0.434700 ;
    PORT
      LAYER met3 ;
        RECT 0.000 240.760 0.600 241.360 ;
    END
  END imem_addr_10
  PIN imem_addr_11
    DIRECTION INPUT ;
    USE SIGNAL ;
    ANTENNAGATEAREA 0.647700 ;
    ANTENNADIFFAREA 0.434700 ;
    PORT
      LAYER met2 ;
        RECT 65.410 319.240 65.690 319.520 ;
    END
  END imem_addr_11
  PIN imem_addr_12
    DIRECTION INPUT ;
    USE SIGNAL ;
    ANTENNAGATEAREA 0.647700 ;
    ANTENNADIFFAREA 0.434700 ;
    PORT
      LAYER met3 ;
        RECT 0.000 227.160 0.600 227.760 ;
    END
  END imem_addr_12
  PIN imem_addr_13
    DIRECTION INPUT ;
    USE SIGNAL ;
    ANTENNAGATEAREA 0.647700 ;
    ANTENNADIFFAREA 0.434700 ;
    PORT
      LAYER met3 ;
        RECT 0.000 209.480 0.600 210.080 ;
    END
  END imem_addr_13
  PIN imem_addr_14
    DIRECTION INPUT ;
    USE SIGNAL ;
    ANTENNAGATEAREA 0.647700 ;
    ANTENNADIFFAREA 0.434700 ;
    PORT
      LAYER met2 ;
        RECT 66.330 319.240 66.610 319.520 ;
    END
  END imem_addr_14
  PIN imem_addr_15
    DIRECTION INPUT ;
    USE SIGNAL ;
    ANTENNAGATEAREA 0.647700 ;
    ANTENNADIFFAREA 0.434700 ;
    PORT
      LAYER met3 ;
        RECT 0.000 146.920 0.600 147.520 ;
    END
  END imem_addr_15
  PIN imem_addr_16
    DIRECTION INPUT ;
    USE SIGNAL ;
    ANTENNAGATEAREA 0.647700 ;
    ANTENNADIFFAREA 0.434700 ;
    PORT
      LAYER met3 ;
        RECT 0.000 238.040 0.600 238.640 ;
    END
  END imem_addr_16
  PIN imem_addr_17
    DIRECTION INPUT ;
    USE SIGNAL ;
    ANTENNAGATEAREA 0.647700 ;
    ANTENNADIFFAREA 0.434700 ;
    PORT
      LAYER met2 ;
        RECT 33.210 319.240 33.490 319.520 ;
    END
  END imem_addr_17
  PIN imem_addr_18
    DIRECTION INPUT ;
    USE SIGNAL ;
    ANTENNAGATEAREA 0.647700 ;
    ANTENNADIFFAREA 0.434700 ;
    PORT
      LAYER met3 ;
        RECT 0.000 259.800 0.600 260.400 ;
    END
  END imem_addr_18
  PIN imem_addr_19
    DIRECTION INPUT ;
    USE SIGNAL ;
    ANTENNAGATEAREA 0.647700 ;
    ANTENNADIFFAREA 0.434700 ;
    PORT
      LAYER met2 ;
        RECT 82.890 319.240 83.170 319.520 ;
    END
  END imem_addr_19
  PIN imem_addr_2
    DIRECTION INPUT ;
    USE SIGNAL ;
    ANTENNAGATEAREA 0.647700 ;
    ANTENNADIFFAREA 0.434700 ;
    PORT
      LAYER met2 ;
        RECT 55.290 319.240 55.570 319.520 ;
    END
  END imem_addr_2
  PIN imem_addr_20
    DIRECTION INPUT ;
    USE SIGNAL ;
    ANTENNAGATEAREA 0.647700 ;
    ANTENNADIFFAREA 0.434700 ;
    PORT
      LAYER met3 ;
        RECT 0.000 236.680 0.600 237.280 ;
    END
  END imem_addr_20
  PIN imem_addr_21
    DIRECTION INPUT ;
    USE SIGNAL ;
    ANTENNAGATEAREA 0.647700 ;
    ANTENNADIFFAREA 0.434700 ;
    PORT
      LAYER met3 ;
        RECT 0.000 224.440 0.600 225.040 ;
    END
  END imem_addr_21
  PIN imem_addr_22
    DIRECTION INPUT ;
    USE SIGNAL ;
    ANTENNAGATEAREA 0.647700 ;
    ANTENNADIFFAREA 0.434700 ;
    PORT
      LAYER met3 ;
        RECT 0.000 191.800 0.600 192.400 ;
    END
  END imem_addr_22
  PIN imem_addr_23
    DIRECTION INPUT ;
    USE SIGNAL ;
    ANTENNAGATEAREA 0.647700 ;
    ANTENNADIFFAREA 0.434700 ;
    PORT
      LAYER met3 ;
        RECT 0.000 160.520 0.600 161.120 ;
    END
  END imem_addr_23
  PIN imem_addr_24
    DIRECTION INPUT ;
    USE SIGNAL ;
    ANTENNAGATEAREA 0.647700 ;
    ANTENNADIFFAREA 0.434700 ;
    PORT
      LAYER met3 ;
        RECT 0.000 174.120 0.600 174.720 ;
    END
  END imem_addr_24
  PIN imem_addr_25
    DIRECTION INPUT ;
    USE SIGNAL ;
    ANTENNAGATEAREA 0.647700 ;
    ANTENNADIFFAREA 0.434700 ;
    PORT
      LAYER met2 ;
        RECT 36.890 319.240 37.170 319.520 ;
    END
  END imem_addr_25
  PIN imem_addr_26
    DIRECTION INPUT ;
    USE SIGNAL ;
    ANTENNAGATEAREA 0.647700 ;
    ANTENNADIFFAREA 0.434700 ;
    PORT
      LAYER met3 ;
        RECT 0.000 243.480 0.600 244.080 ;
    END
  END imem_addr_26
  PIN imem_addr_27
    DIRECTION INPUT ;
    USE SIGNAL ;
    ANTENNAGATEAREA 0.647700 ;
    ANTENNADIFFAREA 0.434700 ;
    PORT
      LAYER met3 ;
        RECT 0.000 204.040 0.600 204.640 ;
    END
  END imem_addr_27
  PIN imem_addr_28
    DIRECTION INPUT ;
    USE SIGNAL ;
    ANTENNAGATEAREA 0.647700 ;
    ANTENNADIFFAREA 0.434700 ;
    PORT
      LAYER met3 ;
        RECT 0.000 151.000 0.600 151.600 ;
    END
  END imem_addr_28
  PIN imem_addr_29
    DIRECTION INPUT ;
    USE SIGNAL ;
    ANTENNAGATEAREA 0.647700 ;
    ANTENNADIFFAREA 0.434700 ;
    PORT
      LAYER met3 ;
        RECT 0.000 193.160 0.600 193.760 ;
    END
  END imem_addr_29
  PIN imem_addr_3
    DIRECTION INPUT ;
    USE SIGNAL ;
    ANTENNAGATEAREA 0.647700 ;
    ANTENNADIFFAREA 0.434700 ;
    PORT
      LAYER met3 ;
        RECT 0.000 176.840 0.600 177.440 ;
    END
  END imem_addr_3
  PIN imem_addr_30
    DIRECTION INPUT ;
    USE SIGNAL ;
    ANTENNAGATEAREA 0.647700 ;
    ANTENNADIFFAREA 0.434700 ;
    PORT
      LAYER met3 ;
        RECT 0.000 172.760 0.600 173.360 ;
    END
  END imem_addr_30
  PIN imem_addr_31
    DIRECTION INPUT ;
    USE SIGNAL ;
    ANTENNAGATEAREA 0.647700 ;
    ANTENNADIFFAREA 0.434700 ;
    PORT
      LAYER met3 ;
        RECT 0.000 142.840 0.600 143.440 ;
    END
  END imem_addr_31
  PIN imem_addr_4
    DIRECTION INPUT ;
    USE SIGNAL ;
    ANTENNAGATEAREA 0.647700 ;
    ANTENNADIFFAREA 0.434700 ;
    PORT
      LAYER met2 ;
        RECT 81.970 319.240 82.250 319.520 ;
    END
  END imem_addr_4
  PIN imem_addr_5
    DIRECTION INPUT ;
    USE SIGNAL ;
    ANTENNAGATEAREA 0.647700 ;
    ANTENNADIFFAREA 0.434700 ;
    PORT
      LAYER met3 ;
        RECT 0.000 233.960 0.600 234.560 ;
    END
  END imem_addr_5
  PIN imem_addr_6
    DIRECTION INPUT ;
    USE SIGNAL ;
    ANTENNAGATEAREA 0.647700 ;
    ANTENNADIFFAREA 0.434700 ;
    PORT
      LAYER met3 ;
        RECT 0.000 229.880 0.600 230.480 ;
    END
  END imem_addr_6
  PIN imem_addr_7
    DIRECTION INPUT ;
    USE SIGNAL ;
    ANTENNAGATEAREA 0.647700 ;
    ANTENNADIFFAREA 0.434700 ;
    PORT
      LAYER met3 ;
        RECT 0.000 223.080 0.600 223.680 ;
    END
  END imem_addr_7
  PIN imem_addr_8
    DIRECTION INPUT ;
    USE SIGNAL ;
    ANTENNAGATEAREA 0.647700 ;
    ANTENNADIFFAREA 0.434700 ;
    PORT
      LAYER met3 ;
        RECT 0.000 141.480 0.600 142.080 ;
    END
  END imem_addr_8
  PIN imem_addr_9
    DIRECTION INPUT ;
    USE SIGNAL ;
    ANTENNAGATEAREA 0.647700 ;
    ANTENNADIFFAREA 0.434700 ;
    PORT
      LAYER met2 ;
        RECT 78.290 319.240 78.570 319.520 ;
    END
  END imem_addr_9
  PIN imem_axi_araddr_0
    DIRECTION OUTPUT ;
    USE SIGNAL ;
    ANTENNAGATEAREA 0.434700 ;
    ANTENNADIFFAREA 1.137600 ;
    PORT
      LAYER met2 ;
        RECT 75.530 319.240 75.810 319.520 ;
    END
  END imem_axi_araddr_0
  PIN imem_axi_araddr_1
    DIRECTION OUTPUT ;
    USE SIGNAL ;
    ANTENNAGATEAREA 0.434700 ;
    ANTENNADIFFAREA 1.137600 ;
    PORT
      LAYER met2 ;
        RECT 40.570 319.240 40.850 319.520 ;
    END
  END imem_axi_araddr_1
  PIN imem_axi_araddr_10
    DIRECTION OUTPUT ;
    USE SIGNAL ;
    ANTENNAGATEAREA 0.434700 ;
    ANTENNADIFFAREA 1.137600 ;
    PORT
      LAYER met3 ;
        RECT 0.000 199.960 0.600 200.560 ;
    END
  END imem_axi_araddr_10
  PIN imem_axi_araddr_11
    DIRECTION OUTPUT ;
    USE SIGNAL ;
    ANTENNAGATEAREA 0.434700 ;
    ANTENNADIFFAREA 1.137600 ;
    PORT
      LAYER met2 ;
        RECT 67.250 319.240 67.530 319.520 ;
    END
  END imem_axi_araddr_11
  PIN imem_axi_araddr_12
    DIRECTION OUTPUT ;
    USE SIGNAL ;
    ANTENNAGATEAREA 0.434700 ;
    ANTENNADIFFAREA 1.137600 ;
    PORT
      LAYER met3 ;
        RECT 0.000 208.120 0.600 208.720 ;
    END
  END imem_axi_araddr_12
  PIN imem_axi_araddr_13
    DIRECTION OUTPUT ;
    USE SIGNAL ;
    ANTENNAGATEAREA 0.434700 ;
    ANTENNADIFFAREA 1.137600 ;
    PORT
      LAYER met3 ;
        RECT 0.000 205.400 0.600 206.000 ;
    END
  END imem_axi_araddr_13
  PIN imem_axi_araddr_14
    DIRECTION OUTPUT ;
    USE SIGNAL ;
    ANTENNAGATEAREA 0.434700 ;
    ANTENNADIFFAREA 1.137600 ;
    PORT
      LAYER met2 ;
        RECT 68.170 319.240 68.450 319.520 ;
    END
  END imem_axi_araddr_14
  PIN imem_axi_araddr_15
    DIRECTION OUTPUT ;
    USE SIGNAL ;
    ANTENNAGATEAREA 0.434700 ;
    ANTENNADIFFAREA 1.137600 ;
    PORT
      LAYER met3 ;
        RECT 0.000 163.240 0.600 163.840 ;
    END
  END imem_axi_araddr_15
  PIN imem_axi_araddr_16
    DIRECTION OUTPUT ;
    USE SIGNAL ;
    ANTENNAGATEAREA 0.434700 ;
    ANTENNADIFFAREA 1.137600 ;
    PORT
      LAYER met3 ;
        RECT 0.000 235.320 0.600 235.920 ;
    END
  END imem_axi_araddr_16
  PIN imem_axi_araddr_17
    DIRECTION OUTPUT ;
    USE SIGNAL ;
    ANTENNAGATEAREA 0.434700 ;
    ANTENNADIFFAREA 1.137600 ;
    PORT
      LAYER met2 ;
        RECT 35.050 319.240 35.330 319.520 ;
    END
  END imem_axi_araddr_17
  PIN imem_axi_araddr_18
    DIRECTION OUTPUT ;
    USE SIGNAL ;
    ANTENNAGATEAREA 0.434700 ;
    ANTENNADIFFAREA 1.137600 ;
    PORT
      LAYER met2 ;
        RECT 23.090 319.240 23.370 319.520 ;
    END
  END imem_axi_araddr_18
  PIN imem_axi_araddr_19
    DIRECTION OUTPUT ;
    USE SIGNAL ;
    ANTENNAGATEAREA 0.434700 ;
    ANTENNADIFFAREA 1.137600 ;
    PORT
      LAYER met2 ;
        RECT 85.650 319.240 85.930 319.520 ;
    END
  END imem_axi_araddr_19
  PIN imem_axi_araddr_2
    DIRECTION OUTPUT ;
    USE SIGNAL ;
    ANTENNAGATEAREA 0.434700 ;
    ANTENNADIFFAREA 1.137600 ;
    PORT
      LAYER met2 ;
        RECT 57.130 319.240 57.410 319.520 ;
    END
  END imem_axi_araddr_2
  PIN imem_axi_araddr_20
    DIRECTION OUTPUT ;
    USE SIGNAL ;
    ANTENNAGATEAREA 0.434700 ;
    ANTENNADIFFAREA 1.137600 ;
    PORT
      LAYER met3 ;
        RECT 0.000 228.520 0.600 229.120 ;
    END
  END imem_axi_araddr_20
  PIN imem_axi_araddr_21
    DIRECTION OUTPUT ;
    USE SIGNAL ;
    ANTENNAGATEAREA 0.434700 ;
    ANTENNADIFFAREA 1.137600 ;
    PORT
      LAYER met3 ;
        RECT 0.000 201.320 0.600 201.920 ;
    END
  END imem_axi_araddr_21
  PIN imem_axi_araddr_22
    DIRECTION OUTPUT ;
    USE SIGNAL ;
    ANTENNAGATEAREA 0.434700 ;
    ANTENNADIFFAREA 1.137600 ;
    PORT
      LAYER met3 ;
        RECT 0.000 195.880 0.600 196.480 ;
    END
  END imem_axi_araddr_22
  PIN imem_axi_araddr_23
    DIRECTION OUTPUT ;
    USE SIGNAL ;
    ANTENNAGATEAREA 0.434700 ;
    ANTENNADIFFAREA 1.137600 ;
    PORT
      LAYER met3 ;
        RECT 0.000 164.600 0.600 165.200 ;
    END
  END imem_axi_araddr_23
  PIN imem_axi_araddr_24
    DIRECTION OUTPUT ;
    USE SIGNAL ;
    ANTENNAGATEAREA 0.434700 ;
    ANTENNADIFFAREA 1.137600 ;
    PORT
      LAYER met3 ;
        RECT 0.000 175.480 0.600 176.080 ;
    END
  END imem_axi_araddr_24
  PIN imem_axi_araddr_25
    DIRECTION OUTPUT ;
    USE SIGNAL ;
    ANTENNAGATEAREA 0.434700 ;
    ANTENNADIFFAREA 1.137600 ;
    PORT
      LAYER met2 ;
        RECT 37.810 319.240 38.090 319.520 ;
    END
  END imem_axi_araddr_25
  PIN imem_axi_araddr_26
    DIRECTION OUTPUT ;
    USE SIGNAL ;
    ANTENNAGATEAREA 0.434700 ;
    ANTENNADIFFAREA 1.137600 ;
    PORT
      LAYER met3 ;
        RECT 0.000 242.120 0.600 242.720 ;
    END
  END imem_axi_araddr_26
  PIN imem_axi_araddr_27
    DIRECTION OUTPUT ;
    USE SIGNAL ;
    ANTENNAGATEAREA 0.434700 ;
    ANTENNADIFFAREA 1.137600 ;
    PORT
      LAYER met3 ;
        RECT 0.000 202.680 0.600 203.280 ;
    END
  END imem_axi_araddr_27
  PIN imem_axi_araddr_28
    DIRECTION OUTPUT ;
    USE SIGNAL ;
    ANTENNAGATEAREA 0.434700 ;
    ANTENNADIFFAREA 1.137600 ;
    PORT
      LAYER met3 ;
        RECT 0.000 168.680 0.600 169.280 ;
    END
  END imem_axi_araddr_28
  PIN imem_axi_araddr_29
    DIRECTION OUTPUT ;
    USE SIGNAL ;
    ANTENNAGATEAREA 0.434700 ;
    ANTENNADIFFAREA 1.137600 ;
    PORT
      LAYER met3 ;
        RECT 0.000 194.520 0.600 195.120 ;
    END
  END imem_axi_araddr_29
  PIN imem_axi_araddr_3
    DIRECTION OUTPUT ;
    USE SIGNAL ;
    ANTENNAGATEAREA 0.434700 ;
    ANTENNADIFFAREA 1.137600 ;
    PORT
      LAYER met3 ;
        RECT 0.000 178.200 0.600 178.800 ;
    END
  END imem_axi_araddr_3
  PIN imem_axi_araddr_30
    DIRECTION OUTPUT ;
    USE SIGNAL ;
    ANTENNAGATEAREA 0.434700 ;
    ANTENNADIFFAREA 1.137600 ;
    PORT
      LAYER met3 ;
        RECT 0.000 127.880 0.600 128.480 ;
    END
  END imem_axi_araddr_30
  PIN imem_axi_araddr_31
    DIRECTION OUTPUT ;
    USE SIGNAL ;
    ANTENNAGATEAREA 0.434700 ;
    ANTENNADIFFAREA 1.137600 ;
    PORT
      LAYER met3 ;
        RECT 0.000 157.800 0.600 158.400 ;
    END
  END imem_axi_araddr_31
  PIN imem_axi_araddr_4
    DIRECTION OUTPUT ;
    USE SIGNAL ;
    ANTENNAGATEAREA 0.434700 ;
    ANTENNADIFFAREA 1.137600 ;
    PORT
      LAYER met2 ;
        RECT 83.810 319.240 84.090 319.520 ;
    END
  END imem_axi_araddr_4
  PIN imem_axi_araddr_5
    DIRECTION OUTPUT ;
    USE SIGNAL ;
    ANTENNAGATEAREA 0.434700 ;
    ANTENNADIFFAREA 1.137600 ;
    PORT
      LAYER met3 ;
        RECT 0.000 232.600 0.600 233.200 ;
    END
  END imem_axi_araddr_5
  PIN imem_axi_araddr_6
    DIRECTION OUTPUT ;
    USE SIGNAL ;
    ANTENNAGATEAREA 0.434700 ;
    ANTENNADIFFAREA 1.137600 ;
    PORT
      LAYER met3 ;
        RECT 0.000 231.240 0.600 231.840 ;
    END
  END imem_axi_araddr_6
  PIN imem_axi_araddr_7
    DIRECTION OUTPUT ;
    USE SIGNAL ;
    ANTENNAGATEAREA 0.434700 ;
    ANTENNADIFFAREA 1.137600 ;
    PORT
      LAYER met3 ;
        RECT 0.000 221.720 0.600 222.320 ;
    END
  END imem_axi_araddr_7
  PIN imem_axi_araddr_8
    DIRECTION OUTPUT ;
    USE SIGNAL ;
    ANTENNAGATEAREA 0.434700 ;
    ANTENNADIFFAREA 1.137600 ;
    PORT
      LAYER met3 ;
        RECT 0.000 165.960 0.600 166.560 ;
    END
  END imem_axi_araddr_8
  PIN imem_axi_araddr_9
    DIRECTION OUTPUT ;
    USE SIGNAL ;
    ANTENNAGATEAREA 0.434700 ;
    ANTENNADIFFAREA 1.137600 ;
    PORT
      LAYER met2 ;
        RECT 79.210 319.240 79.490 319.520 ;
    END
  END imem_axi_araddr_9
  PIN imem_axi_arready
    DIRECTION INPUT ;
    USE SIGNAL ;
    ANTENNAGATEAREA 0.647700 ;
    ANTENNADIFFAREA 0.434700 ;
    PORT
      LAYER met3 ;
        RECT 0.000 180.920 0.600 181.520 ;
    END
  END imem_axi_arready
  PIN imem_axi_arvalid
    DIRECTION OUTPUT ;
    USE SIGNAL ;
    ANTENNAGATEAREA 0.434700 ;
    ANTENNADIFFAREA 1.137600 ;
    PORT
      LAYER met3 ;
        RECT 0.000 187.720 0.600 188.320 ;
    END
  END imem_axi_arvalid
  PIN imem_axi_awaddr_0
    DIRECTION OUTPUT ;
    USE SIGNAL ;
    ANTENNAGATEAREA 0.434700 ;
    ANTENNADIFFAREA 0.434700 ;
    PORT
      LAYER met3 ;
        RECT 0.000 149.640 0.600 150.240 ;
    END
  END imem_axi_awaddr_0
  PIN imem_axi_awaddr_1
    DIRECTION OUTPUT ;
    USE SIGNAL ;
    ANTENNAGATEAREA 0.434700 ;
    ANTENNADIFFAREA 0.775300 ;
    PORT
      LAYER met2 ;
        RECT 202.490 319.240 202.770 319.520 ;
    END
  END imem_axi_awaddr_1
  PIN imem_axi_awaddr_10
    DIRECTION OUTPUT ;
    USE SIGNAL ;
    ANTENNAGATEAREA 0.434700 ;
    ANTENNADIFFAREA 0.775300 ;
    PORT
      LAYER met2 ;
        RECT 192.370 319.240 192.650 319.520 ;
    END
  END imem_axi_awaddr_10
  PIN imem_axi_awaddr_11
    DIRECTION OUTPUT ;
    USE SIGNAL ;
    ANTENNAGATEAREA 0.434700 ;
    ANTENNADIFFAREA 0.775300 ;
    PORT
      LAYER met2 ;
        RECT 189.610 319.240 189.890 319.520 ;
    END
  END imem_axi_awaddr_11
  PIN imem_axi_awaddr_12
    DIRECTION OUTPUT ;
    USE SIGNAL ;
    ANTENNAGATEAREA 0.434700 ;
    ANTENNADIFFAREA 0.775300 ;
    PORT
      LAYER met2 ;
        RECT 132.570 319.240 132.850 319.520 ;
    END
  END imem_axi_awaddr_12
  PIN imem_axi_awaddr_13
    DIRECTION OUTPUT ;
    USE SIGNAL ;
    ANTENNAGATEAREA 0.434700 ;
    ANTENNADIFFAREA 0.775300 ;
    PORT
      LAYER met2 ;
        RECT 157.410 319.240 157.690 319.520 ;
    END
  END imem_axi_awaddr_13
  PIN imem_axi_awaddr_14
    DIRECTION OUTPUT ;
    USE SIGNAL ;
    ANTENNAGATEAREA 0.434700 ;
    ANTENNADIFFAREA 0.775300 ;
    PORT
      LAYER met2 ;
        RECT 179.490 319.240 179.770 319.520 ;
    END
  END imem_axi_awaddr_14
  PIN imem_axi_awaddr_15
    DIRECTION OUTPUT ;
    USE SIGNAL ;
    ANTENNAGATEAREA 0.434700 ;
    ANTENNADIFFAREA 0.775300 ;
    PORT
      LAYER met2 ;
        RECT 190.530 319.240 190.810 319.520 ;
    END
  END imem_axi_awaddr_15
  PIN imem_axi_awaddr_16
    DIRECTION OUTPUT ;
    USE SIGNAL ;
    ANTENNAGATEAREA 0.434700 ;
    ANTENNADIFFAREA 0.775300 ;
    PORT
      LAYER met2 ;
        RECT 144.530 319.240 144.810 319.520 ;
    END
  END imem_axi_awaddr_16
  PIN imem_axi_awaddr_17
    DIRECTION OUTPUT ;
    USE SIGNAL ;
    ANTENNAGATEAREA 0.434700 ;
    ANTENNADIFFAREA 0.775300 ;
    PORT
      LAYER met2 ;
        RECT 176.730 319.240 177.010 319.520 ;
    END
  END imem_axi_awaddr_17
  PIN imem_axi_awaddr_18
    DIRECTION OUTPUT ;
    USE SIGNAL ;
    ANTENNAGATEAREA 0.434700 ;
    ANTENNADIFFAREA 0.775300 ;
    PORT
      LAYER met2 ;
        RECT 193.290 319.240 193.570 319.520 ;
    END
  END imem_axi_awaddr_18
  PIN imem_axi_awaddr_19
    DIRECTION OUTPUT ;
    USE SIGNAL ;
    ANTENNAGATEAREA 0.434700 ;
    ANTENNADIFFAREA 0.775300 ;
    PORT
      LAYER met2 ;
        RECT 200.650 319.240 200.930 319.520 ;
    END
  END imem_axi_awaddr_19
  PIN imem_axi_awaddr_2
    DIRECTION OUTPUT ;
    USE SIGNAL ;
    ANTENNAGATEAREA 0.434700 ;
    ANTENNADIFFAREA 0.775300 ;
    PORT
      LAYER met2 ;
        RECT 177.650 319.240 177.930 319.520 ;
    END
  END imem_axi_awaddr_2
  PIN imem_axi_awaddr_20
    DIRECTION OUTPUT ;
    USE SIGNAL ;
    ANTENNAGATEAREA 0.434700 ;
    ANTENNADIFFAREA 0.775300 ;
    PORT
      LAYER met2 ;
        RECT 183.170 319.240 183.450 319.520 ;
    END
  END imem_axi_awaddr_20
  PIN imem_axi_awaddr_21
    DIRECTION OUTPUT ;
    USE SIGNAL ;
    ANTENNAGATEAREA 0.434700 ;
    ANTENNADIFFAREA 0.775300 ;
    PORT
      LAYER met2 ;
        RECT 184.090 319.240 184.370 319.520 ;
    END
  END imem_axi_awaddr_21
  PIN imem_axi_awaddr_22
    DIRECTION OUTPUT ;
    USE SIGNAL ;
    ANTENNAGATEAREA 0.434700 ;
    ANTENNADIFFAREA 0.775300 ;
    PORT
      LAYER met2 ;
        RECT 156.490 319.240 156.770 319.520 ;
    END
  END imem_axi_awaddr_22
  PIN imem_axi_awaddr_23
    DIRECTION OUTPUT ;
    USE SIGNAL ;
    ANTENNAGATEAREA 0.434700 ;
    ANTENNADIFFAREA 0.775300 ;
    PORT
      LAYER met2 ;
        RECT 227.330 319.240 227.610 319.520 ;
    END
  END imem_axi_awaddr_23
  PIN imem_axi_awaddr_24
    DIRECTION OUTPUT ;
    USE SIGNAL ;
    ANTENNAGATEAREA 0.434700 ;
    ANTENNADIFFAREA 0.775300 ;
    PORT
      LAYER met2 ;
        RECT 201.570 319.240 201.850 319.520 ;
    END
  END imem_axi_awaddr_24
  PIN imem_axi_awaddr_25
    DIRECTION OUTPUT ;
    USE SIGNAL ;
    ANTENNAGATEAREA 0.434700 ;
    ANTENNADIFFAREA 0.775300 ;
    PORT
      LAYER met2 ;
        RECT 158.330 319.240 158.610 319.520 ;
    END
  END imem_axi_awaddr_25
  PIN imem_axi_awaddr_26
    DIRECTION OUTPUT ;
    USE SIGNAL ;
    ANTENNAGATEAREA 0.434700 ;
    ANTENNADIFFAREA 0.775300 ;
    PORT
      LAYER met2 ;
        RECT 185.010 319.240 185.290 319.520 ;
    END
  END imem_axi_awaddr_26
  PIN imem_axi_awaddr_27
    DIRECTION OUTPUT ;
    USE SIGNAL ;
    ANTENNAGATEAREA 0.434700 ;
    ANTENNADIFFAREA 0.775300 ;
    PORT
      LAYER met2 ;
        RECT 141.770 319.240 142.050 319.520 ;
    END
  END imem_axi_awaddr_27
  PIN imem_axi_awaddr_28
    DIRECTION OUTPUT ;
    USE SIGNAL ;
    ANTENNAGATEAREA 0.434700 ;
    ANTENNADIFFAREA 0.775300 ;
    PORT
      LAYER met2 ;
        RECT 194.210 319.240 194.490 319.520 ;
    END
  END imem_axi_awaddr_28
  PIN imem_axi_awaddr_29
    DIRECTION OUTPUT ;
    USE SIGNAL ;
    ANTENNAGATEAREA 0.434700 ;
    ANTENNADIFFAREA 0.775300 ;
    PORT
      LAYER met2 ;
        RECT 146.370 319.240 146.650 319.520 ;
    END
  END imem_axi_awaddr_29
  PIN imem_axi_awaddr_3
    DIRECTION OUTPUT ;
    USE SIGNAL ;
    ANTENNAGATEAREA 0.434700 ;
    ANTENNADIFFAREA 0.775300 ;
    PORT
      LAYER met2 ;
        RECT 185.930 319.240 186.210 319.520 ;
    END
  END imem_axi_awaddr_3
  PIN imem_axi_awaddr_30
    DIRECTION OUTPUT ;
    USE SIGNAL ;
    ANTENNAGATEAREA 0.434700 ;
    ANTENNADIFFAREA 0.775300 ;
    PORT
      LAYER met2 ;
        RECT 166.610 319.240 166.890 319.520 ;
    END
  END imem_axi_awaddr_30
  PIN imem_axi_awaddr_31
    DIRECTION OUTPUT ;
    USE SIGNAL ;
    ANTENNAGATEAREA 0.434700 ;
    ANTENNADIFFAREA 0.775300 ;
    PORT
      LAYER met2 ;
        RECT 155.570 319.240 155.850 319.520 ;
    END
  END imem_axi_awaddr_31
  PIN imem_axi_awaddr_4
    DIRECTION OUTPUT ;
    USE SIGNAL ;
    ANTENNAGATEAREA 0.434700 ;
    ANTENNADIFFAREA 0.775300 ;
    PORT
      LAYER met2 ;
        RECT 195.130 319.240 195.410 319.520 ;
    END
  END imem_axi_awaddr_4
  PIN imem_axi_awaddr_5
    DIRECTION OUTPUT ;
    USE SIGNAL ;
    ANTENNAGATEAREA 0.434700 ;
    ANTENNADIFFAREA 0.775300 ;
    PORT
      LAYER met2 ;
        RECT 140.850 319.240 141.130 319.520 ;
    END
  END imem_axi_awaddr_5
  PIN imem_axi_awaddr_6
    DIRECTION OUTPUT ;
    USE SIGNAL ;
    ANTENNAGATEAREA 0.434700 ;
    ANTENNADIFFAREA 0.775300 ;
    PORT
      LAYER met2 ;
        RECT 203.410 319.240 203.690 319.520 ;
    END
  END imem_axi_awaddr_6
  PIN imem_axi_awaddr_7
    DIRECTION OUTPUT ;
    USE SIGNAL ;
    ANTENNAGATEAREA 0.434700 ;
    ANTENNADIFFAREA 0.775300 ;
    PORT
      LAYER met2 ;
        RECT 173.970 319.240 174.250 319.520 ;
    END
  END imem_axi_awaddr_7
  PIN imem_axi_awaddr_8
    DIRECTION OUTPUT ;
    USE SIGNAL ;
    ANTENNAGATEAREA 0.434700 ;
    ANTENNADIFFAREA 0.775300 ;
    PORT
      LAYER met2 ;
        RECT 154.650 319.240 154.930 319.520 ;
    END
  END imem_axi_awaddr_8
  PIN imem_axi_awaddr_9
    DIRECTION OUTPUT ;
    USE SIGNAL ;
    ANTENNAGATEAREA 0.434700 ;
    ANTENNADIFFAREA 0.775300 ;
    PORT
      LAYER met2 ;
        RECT 196.050 319.240 196.330 319.520 ;
    END
  END imem_axi_awaddr_9
  PIN imem_axi_awready
    DIRECTION INPUT ;
    USE SIGNAL ;
    PORT
      LAYER met2 ;
        RECT 5.610 0.000 5.890 0.280 ;
    END
  END imem_axi_awready
  PIN imem_axi_awvalid
    DIRECTION OUTPUT ;
    USE SIGNAL ;
    ANTENNAGATEAREA 0.434700 ;
    ANTENNADIFFAREA 0.775300 ;
    PORT
      LAYER met2 ;
        RECT 186.850 319.240 187.130 319.520 ;
    END
  END imem_axi_awvalid
  PIN imem_axi_bready
    DIRECTION OUTPUT ;
    USE SIGNAL ;
    ANTENNAGATEAREA 0.434700 ;
    ANTENNADIFFAREA 0.775300 ;
    PORT
      LAYER met3 ;
        RECT 0.000 155.080 0.600 155.680 ;
    END
  END imem_axi_bready
  PIN imem_axi_bresp_0
    DIRECTION INPUT ;
    USE SIGNAL ;
    PORT
      LAYER met2 ;
        RECT 6.530 0.000 6.810 0.280 ;
    END
  END imem_axi_bresp_0
  PIN imem_axi_bresp_1
    DIRECTION INPUT ;
    USE SIGNAL ;
    PORT
      LAYER met2 ;
        RECT 7.450 0.000 7.730 0.280 ;
    END
  END imem_axi_bresp_1
  PIN imem_axi_bvalid
    DIRECTION INPUT ;
    USE SIGNAL ;
    PORT
      LAYER met2 ;
        RECT 8.370 0.000 8.650 0.280 ;
    END
  END imem_axi_bvalid
  PIN imem_axi_rdata_0
    DIRECTION INPUT ;
    USE SIGNAL ;
    ANTENNAGATEAREA 0.647700 ;
    ANTENNADIFFAREA 0.434700 ;
    PORT
      LAYER met2 ;
        RECT 150.970 319.240 151.250 319.520 ;
    END
  END imem_axi_rdata_0
  PIN imem_axi_rdata_1
    DIRECTION INPUT ;
    USE SIGNAL ;
    ANTENNAGATEAREA 0.647700 ;
    ANTENNADIFFAREA 0.434700 ;
    PORT
      LAYER met2 ;
        RECT 117.850 319.240 118.130 319.520 ;
    END
  END imem_axi_rdata_1
  PIN imem_axi_rdata_10
    DIRECTION INPUT ;
    USE SIGNAL ;
    ANTENNAGATEAREA 0.647700 ;
    ANTENNADIFFAREA 0.434700 ;
    PORT
      LAYER met3 ;
        RECT 0.000 186.360 0.600 186.960 ;
    END
  END imem_axi_rdata_10
  PIN imem_axi_rdata_11
    DIRECTION INPUT ;
    USE SIGNAL ;
    ANTENNAGATEAREA 0.647700 ;
    ANTENNADIFFAREA 0.434700 ;
    PORT
      LAYER met2 ;
        RECT 139.010 319.240 139.290 319.520 ;
    END
  END imem_axi_rdata_11
  PIN imem_axi_rdata_12
    DIRECTION INPUT ;
    USE SIGNAL ;
    ANTENNAGATEAREA 0.647700 ;
    ANTENNADIFFAREA 0.434700 ;
    PORT
      LAYER met2 ;
        RECT 104.050 319.240 104.330 319.520 ;
    END
  END imem_axi_rdata_12
  PIN imem_axi_rdata_13
    DIRECTION INPUT ;
    USE SIGNAL ;
    ANTENNAGATEAREA 0.647700 ;
    ANTENNADIFFAREA 0.434700 ;
    PORT
      LAYER met2 ;
        RECT 119.690 319.240 119.970 319.520 ;
    END
  END imem_axi_rdata_13
  PIN imem_axi_rdata_14
    DIRECTION INPUT ;
    USE SIGNAL ;
    ANTENNAGATEAREA 0.647700 ;
    ANTENNADIFFAREA 0.434700 ;
    PORT
      LAYER met2 ;
        RECT 161.090 319.240 161.370 319.520 ;
    END
  END imem_axi_rdata_14
  PIN imem_axi_rdata_15
    DIRECTION INPUT ;
    USE SIGNAL ;
    ANTENNAGATEAREA 0.647700 ;
    ANTENNADIFFAREA 0.434700 ;
    PORT
      LAYER met2 ;
        RECT 173.050 319.240 173.330 319.520 ;
    END
  END imem_axi_rdata_15
  PIN imem_axi_rdata_16
    DIRECTION INPUT ;
    USE SIGNAL ;
    ANTENNAGATEAREA 0.647700 ;
    ANTENNADIFFAREA 0.434700 ;
    PORT
      LAYER met2 ;
        RECT 171.210 319.240 171.490 319.520 ;
    END
  END imem_axi_rdata_16
  PIN imem_axi_rdata_17
    DIRECTION INPUT ;
    USE SIGNAL ;
    ANTENNAGATEAREA 0.647700 ;
    ANTENNADIFFAREA 0.434700 ;
    PORT
      LAYER met3 ;
        RECT 0.000 185.000 0.600 185.600 ;
    END
  END imem_axi_rdata_17
  PIN imem_axi_rdata_18
    DIRECTION INPUT ;
    USE SIGNAL ;
    ANTENNAGATEAREA 0.647700 ;
    ANTENNADIFFAREA 0.434700 ;
    PORT
      LAYER met2 ;
        RECT 153.730 319.240 154.010 319.520 ;
    END
  END imem_axi_rdata_18
  PIN imem_axi_rdata_19
    DIRECTION INPUT ;
    USE SIGNAL ;
    ANTENNAGATEAREA 0.647700 ;
    ANTENNADIFFAREA 0.434700 ;
    PORT
      LAYER met2 ;
        RECT 168.450 319.240 168.730 319.520 ;
    END
  END imem_axi_rdata_19
  PIN imem_axi_rdata_2
    DIRECTION INPUT ;
    USE SIGNAL ;
    ANTENNAGATEAREA 0.647700 ;
    ANTENNADIFFAREA 0.434700 ;
    PORT
      LAYER met2 ;
        RECT 105.890 319.240 106.170 319.520 ;
    END
  END imem_axi_rdata_2
  PIN imem_axi_rdata_20
    DIRECTION INPUT ;
    USE SIGNAL ;
    ANTENNAGATEAREA 0.647700 ;
    ANTENNADIFFAREA 0.434700 ;
    PORT
      LAYER met2 ;
        RECT 104.970 319.240 105.250 319.520 ;
    END
  END imem_axi_rdata_20
  PIN imem_axi_rdata_21
    DIRECTION INPUT ;
    USE SIGNAL ;
    ANTENNAGATEAREA 0.647700 ;
    ANTENNADIFFAREA 0.434700 ;
    PORT
      LAYER met2 ;
        RECT 136.250 319.240 136.530 319.520 ;
    END
  END imem_axi_rdata_21
  PIN imem_axi_rdata_22
    DIRECTION INPUT ;
    USE SIGNAL ;
    ANTENNAGATEAREA 0.647700 ;
    ANTENNADIFFAREA 0.434700 ;
    PORT
      LAYER met2 ;
        RECT 174.890 319.240 175.170 319.520 ;
    END
  END imem_axi_rdata_22
  PIN imem_axi_rdata_23
    DIRECTION INPUT ;
    USE SIGNAL ;
    ANTENNAGATEAREA 0.647700 ;
    ANTENNADIFFAREA 0.434700 ;
    PORT
      LAYER met3 ;
        RECT 0.000 216.280 0.600 216.880 ;
    END
  END imem_axi_rdata_23
  PIN imem_axi_rdata_24
    DIRECTION INPUT ;
    USE SIGNAL ;
    ANTENNAGATEAREA 0.647700 ;
    ANTENNADIFFAREA 0.434700 ;
    PORT
      LAYER met3 ;
        RECT 0.000 220.360 0.600 220.960 ;
    END
  END imem_axi_rdata_24
  PIN imem_axi_rdata_25
    DIRECTION INPUT ;
    USE SIGNAL ;
    ANTENNAGATEAREA 0.647700 ;
    ANTENNADIFFAREA 0.434700 ;
    PORT
      LAYER met3 ;
        RECT 0.000 213.560 0.600 214.160 ;
    END
  END imem_axi_rdata_25
  PIN imem_axi_rdata_26
    DIRECTION INPUT ;
    USE SIGNAL ;
    ANTENNAGATEAREA 0.647700 ;
    ANTENNADIFFAREA 0.434700 ;
    PORT
      LAYER met3 ;
        RECT 0.000 239.400 0.600 240.000 ;
    END
  END imem_axi_rdata_26
  PIN imem_axi_rdata_27
    DIRECTION INPUT ;
    USE SIGNAL ;
    ANTENNAGATEAREA 0.647700 ;
    ANTENNADIFFAREA 0.434700 ;
    PORT
      LAYER met2 ;
        RECT 139.930 319.240 140.210 319.520 ;
    END
  END imem_axi_rdata_27
  PIN imem_axi_rdata_28
    DIRECTION INPUT ;
    USE SIGNAL ;
    ANTENNAGATEAREA 0.647700 ;
    ANTENNADIFFAREA 0.434700 ;
    PORT
      LAYER met3 ;
        RECT 0.000 210.840 0.600 211.440 ;
    END
  END imem_axi_rdata_28
  PIN imem_axi_rdata_29
    DIRECTION INPUT ;
    USE SIGNAL ;
    ANTENNAGATEAREA 0.647700 ;
    ANTENNADIFFAREA 0.434700 ;
    PORT
      LAYER met3 ;
        RECT 0.000 161.880 0.600 162.480 ;
    END
  END imem_axi_rdata_29
  PIN imem_axi_rdata_3
    DIRECTION INPUT ;
    USE SIGNAL ;
    ANTENNAGATEAREA 0.647700 ;
    ANTENNADIFFAREA 0.434700 ;
    PORT
      LAYER met2 ;
        RECT 152.810 319.240 153.090 319.520 ;
    END
  END imem_axi_rdata_3
  PIN imem_axi_rdata_30
    DIRECTION INPUT ;
    USE SIGNAL ;
    ANTENNAGATEAREA 0.647700 ;
    ANTENNADIFFAREA 0.434700 ;
    PORT
      LAYER met3 ;
        RECT 0.000 137.400 0.600 138.000 ;
    END
  END imem_axi_rdata_30
  PIN imem_axi_rdata_31
    DIRECTION INPUT ;
    USE SIGNAL ;
    ANTENNAGATEAREA 0.647700 ;
    ANTENNADIFFAREA 0.434700 ;
    PORT
      LAYER met3 ;
        RECT 0.000 140.120 0.600 140.720 ;
    END
  END imem_axi_rdata_31
  PIN imem_axi_rdata_4
    DIRECTION INPUT ;
    USE SIGNAL ;
    ANTENNAGATEAREA 0.647700 ;
    ANTENNADIFFAREA 0.434700 ;
    PORT
      LAYER met3 ;
        RECT 0.000 197.240 0.600 197.840 ;
    END
  END imem_axi_rdata_4
  PIN imem_axi_rdata_5
    DIRECTION INPUT ;
    USE SIGNAL ;
    ANTENNAGATEAREA 0.647700 ;
    ANTENNADIFFAREA 0.434700 ;
    PORT
      LAYER met3 ;
        RECT 0.000 189.080 0.600 189.680 ;
    END
  END imem_axi_rdata_5
  PIN imem_axi_rdata_6
    DIRECTION INPUT ;
    USE SIGNAL ;
    ANTENNAGATEAREA 0.647700 ;
    ANTENNADIFFAREA 0.434700 ;
    PORT
      LAYER met2 ;
        RECT 118.770 319.240 119.050 319.520 ;
    END
  END imem_axi_rdata_6
  PIN imem_axi_rdata_7
    DIRECTION INPUT ;
    USE SIGNAL ;
    ANTENNAGATEAREA 0.647700 ;
    ANTENNADIFFAREA 0.434700 ;
    PORT
      LAYER met2 ;
        RECT 133.490 319.240 133.770 319.520 ;
    END
  END imem_axi_rdata_7
  PIN imem_axi_rdata_8
    DIRECTION INPUT ;
    USE SIGNAL ;
    ANTENNAGATEAREA 0.647700 ;
    ANTENNADIFFAREA 0.434700 ;
    PORT
      LAYER met2 ;
        RECT 107.730 319.240 108.010 319.520 ;
    END
  END imem_axi_rdata_8
  PIN imem_axi_rdata_9
    DIRECTION INPUT ;
    USE SIGNAL ;
    ANTENNAGATEAREA 0.647700 ;
    ANTENNADIFFAREA 0.434700 ;
    PORT
      LAYER met3 ;
        RECT 0.000 214.920 0.600 215.520 ;
    END
  END imem_axi_rdata_9
  PIN imem_axi_rready
    DIRECTION OUTPUT ;
    USE SIGNAL ;
    ANTENNAGATEAREA 0.434700 ;
    ANTENNADIFFAREA 1.137600 ;
    PORT
      LAYER met3 ;
        RECT 0.000 179.560 0.600 180.160 ;
    END
  END imem_axi_rready
  PIN imem_axi_rresp_0
    DIRECTION INPUT ;
    USE SIGNAL ;
    PORT
      LAYER met2 ;
        RECT 9.290 0.000 9.570 0.280 ;
    END
  END imem_axi_rresp_0
  PIN imem_axi_rresp_1
    DIRECTION INPUT ;
    USE SIGNAL ;
    PORT
      LAYER met2 ;
        RECT 10.210 0.000 10.490 0.280 ;
    END
  END imem_axi_rresp_1
  PIN imem_axi_rvalid
    DIRECTION INPUT ;
    USE SIGNAL ;
    ANTENNAGATEAREA 0.647700 ;
    ANTENNADIFFAREA 0.434700 ;
    PORT
      LAYER met3 ;
        RECT 0.000 159.160 0.600 159.760 ;
    END
  END imem_axi_rvalid
  PIN imem_axi_wdata_0
    DIRECTION OUTPUT ;
    USE SIGNAL ;
    ANTENNAGATEAREA 0.434700 ;
    ANTENNADIFFAREA 0.775300 ;
    PORT
      LAYER met2 ;
        RECT 204.330 319.240 204.610 319.520 ;
    END
  END imem_axi_wdata_0
  PIN imem_axi_wdata_1
    DIRECTION OUTPUT ;
    USE SIGNAL ;
    ANTENNAGATEAREA 0.434700 ;
    ANTENNADIFFAREA 0.775300 ;
    PORT
      LAYER met2 ;
        RECT 205.250 319.240 205.530 319.520 ;
    END
  END imem_axi_wdata_1
  PIN imem_axi_wdata_10
    DIRECTION OUTPUT ;
    USE SIGNAL ;
    ANTENNAGATEAREA 0.434700 ;
    ANTENNADIFFAREA 0.775300 ;
    PORT
      LAYER met2 ;
        RECT 206.170 319.240 206.450 319.520 ;
    END
  END imem_axi_wdata_10
  PIN imem_axi_wdata_11
    DIRECTION OUTPUT ;
    USE SIGNAL ;
    ANTENNAGATEAREA 0.434700 ;
    ANTENNADIFFAREA 0.775300 ;
    PORT
      LAYER met2 ;
        RECT 181.330 319.240 181.610 319.520 ;
    END
  END imem_axi_wdata_11
  PIN imem_axi_wdata_12
    DIRECTION OUTPUT ;
    USE SIGNAL ;
    ANTENNAGATEAREA 0.434700 ;
    ANTENNADIFFAREA 0.775300 ;
    PORT
      LAYER met2 ;
        RECT 196.970 319.240 197.250 319.520 ;
    END
  END imem_axi_wdata_12
  PIN imem_axi_wdata_13
    DIRECTION OUTPUT ;
    USE SIGNAL ;
    ANTENNAGATEAREA 0.434700 ;
    ANTENNADIFFAREA 0.775300 ;
    PORT
      LAYER met2 ;
        RECT 180.410 319.240 180.690 319.520 ;
    END
  END imem_axi_wdata_13
  PIN imem_axi_wdata_14
    DIRECTION OUTPUT ;
    USE SIGNAL ;
    ANTENNAGATEAREA 0.434700 ;
    ANTENNADIFFAREA 0.775300 ;
    PORT
      LAYER met2 ;
        RECT 197.890 319.240 198.170 319.520 ;
    END
  END imem_axi_wdata_14
  PIN imem_axi_wdata_15
    DIRECTION OUTPUT ;
    USE SIGNAL ;
    ANTENNAGATEAREA 0.434700 ;
    ANTENNADIFFAREA 0.775300 ;
    PORT
      LAYER met2 ;
        RECT 175.810 319.240 176.090 319.520 ;
    END
  END imem_axi_wdata_15
  PIN imem_axi_wdata_16
    DIRECTION OUTPUT ;
    USE SIGNAL ;
    ANTENNAGATEAREA 0.434700 ;
    ANTENNADIFFAREA 0.775300 ;
    PORT
      LAYER met2 ;
        RECT 198.810 319.240 199.090 319.520 ;
    END
  END imem_axi_wdata_16
  PIN imem_axi_wdata_17
    DIRECTION OUTPUT ;
    USE SIGNAL ;
    ANTENNAGATEAREA 0.434700 ;
    ANTENNADIFFAREA 0.775300 ;
    PORT
      LAYER met2 ;
        RECT 187.770 319.240 188.050 319.520 ;
    END
  END imem_axi_wdata_17
  PIN imem_axi_wdata_18
    DIRECTION OUTPUT ;
    USE SIGNAL ;
    ANTENNAGATEAREA 0.434700 ;
    ANTENNADIFFAREA 0.775300 ;
    PORT
      LAYER met2 ;
        RECT 167.530 319.240 167.810 319.520 ;
    END
  END imem_axi_wdata_18
  PIN imem_axi_wdata_19
    DIRECTION OUTPUT ;
    USE SIGNAL ;
    ANTENNAGATEAREA 0.434700 ;
    ANTENNADIFFAREA 0.775300 ;
    PORT
      LAYER met2 ;
        RECT 228.250 319.240 228.530 319.520 ;
    END
  END imem_axi_wdata_19
  PIN imem_axi_wdata_2
    DIRECTION OUTPUT ;
    USE SIGNAL ;
    ANTENNAGATEAREA 0.434700 ;
    ANTENNADIFFAREA 0.775300 ;
    PORT
      LAYER met2 ;
        RECT 135.330 319.240 135.610 319.520 ;
    END
  END imem_axi_wdata_2
  PIN imem_axi_wdata_20
    DIRECTION OUTPUT ;
    USE SIGNAL ;
    ANTENNAGATEAREA 0.434700 ;
    ANTENNADIFFAREA 0.775300 ;
    PORT
      LAYER met2 ;
        RECT 162.010 319.240 162.290 319.520 ;
    END
  END imem_axi_wdata_20
  PIN imem_axi_wdata_21
    DIRECTION OUTPUT ;
    USE SIGNAL ;
    ANTENNAGATEAREA 0.434700 ;
    ANTENNADIFFAREA 0.775300 ;
    PORT
      LAYER met2 ;
        RECT 150.050 319.240 150.330 319.520 ;
    END
  END imem_axi_wdata_21
  PIN imem_axi_wdata_22
    DIRECTION OUTPUT ;
    USE SIGNAL ;
    ANTENNAGATEAREA 0.434700 ;
    ANTENNADIFFAREA 0.775300 ;
    PORT
      LAYER met2 ;
        RECT 207.090 319.240 207.370 319.520 ;
    END
  END imem_axi_wdata_22
  PIN imem_axi_wdata_23
    DIRECTION OUTPUT ;
    USE SIGNAL ;
    ANTENNAGATEAREA 0.434700 ;
    ANTENNADIFFAREA 0.775300 ;
    PORT
      LAYER met2 ;
        RECT 162.930 319.240 163.210 319.520 ;
    END
  END imem_axi_wdata_23
  PIN imem_axi_wdata_24
    DIRECTION OUTPUT ;
    USE SIGNAL ;
    ANTENNAGATEAREA 0.434700 ;
    ANTENNADIFFAREA 0.775300 ;
    PORT
      LAYER met2 ;
        RECT 188.690 319.240 188.970 319.520 ;
    END
  END imem_axi_wdata_24
  PIN imem_axi_wdata_25
    DIRECTION OUTPUT ;
    USE SIGNAL ;
    ANTENNAGATEAREA 0.434700 ;
    ANTENNADIFFAREA 0.775300 ;
    PORT
      LAYER met2 ;
        RECT 178.570 319.240 178.850 319.520 ;
    END
  END imem_axi_wdata_25
  PIN imem_axi_wdata_26
    DIRECTION OUTPUT ;
    USE SIGNAL ;
    ANTENNAGATEAREA 0.434700 ;
    ANTENNADIFFAREA 0.775300 ;
    PORT
      LAYER met2 ;
        RECT 222.730 319.240 223.010 319.520 ;
    END
  END imem_axi_wdata_26
  PIN imem_axi_wdata_27
    DIRECTION OUTPUT ;
    USE SIGNAL ;
    ANTENNAGATEAREA 0.434700 ;
    ANTENNADIFFAREA 0.775300 ;
    PORT
      LAYER met2 ;
        RECT 148.210 319.240 148.490 319.520 ;
    END
  END imem_axi_wdata_27
  PIN imem_axi_wdata_28
    DIRECTION OUTPUT ;
    USE SIGNAL ;
    ANTENNAGATEAREA 0.434700 ;
    ANTENNADIFFAREA 0.775300 ;
    PORT
      LAYER met2 ;
        RECT 224.570 319.240 224.850 319.520 ;
    END
  END imem_axi_wdata_28
  PIN imem_axi_wdata_29
    DIRECTION OUTPUT ;
    USE SIGNAL ;
    ANTENNAGATEAREA 0.434700 ;
    ANTENNADIFFAREA 0.775300 ;
    PORT
      LAYER met2 ;
        RECT 219.970 319.240 220.250 319.520 ;
    END
  END imem_axi_wdata_29
  PIN imem_axi_wdata_3
    DIRECTION OUTPUT ;
    USE SIGNAL ;
    ANTENNAGATEAREA 0.434700 ;
    ANTENNADIFFAREA 0.775300 ;
    PORT
      LAYER met2 ;
        RECT 172.130 319.240 172.410 319.520 ;
    END
  END imem_axi_wdata_3
  PIN imem_axi_wdata_30
    DIRECTION OUTPUT ;
    USE SIGNAL ;
    ANTENNAGATEAREA 0.434700 ;
    ANTENNADIFFAREA 0.775300 ;
    PORT
      LAYER met2 ;
        RECT 165.690 319.240 165.970 319.520 ;
    END
  END imem_axi_wdata_30
  PIN imem_axi_wdata_31
    DIRECTION OUTPUT ;
    USE SIGNAL ;
    ANTENNAGATEAREA 0.434700 ;
    ANTENNADIFFAREA 0.775300 ;
    PORT
      LAYER met2 ;
        RECT 199.730 319.240 200.010 319.520 ;
    END
  END imem_axi_wdata_31
  PIN imem_axi_wdata_4
    DIRECTION OUTPUT ;
    USE SIGNAL ;
    ANTENNAGATEAREA 0.434700 ;
    ANTENNADIFFAREA 0.775300 ;
    PORT
      LAYER met2 ;
        RECT 225.490 319.240 225.770 319.520 ;
    END
  END imem_axi_wdata_4
  PIN imem_axi_wdata_5
    DIRECTION OUTPUT ;
    USE SIGNAL ;
    ANTENNAGATEAREA 0.434700 ;
    ANTENNADIFFAREA 0.775300 ;
    PORT
      LAYER met2 ;
        RECT 182.250 319.240 182.530 319.520 ;
    END
  END imem_axi_wdata_5
  PIN imem_axi_wdata_6
    DIRECTION OUTPUT ;
    USE SIGNAL ;
    ANTENNAGATEAREA 0.434700 ;
    ANTENNADIFFAREA 0.775300 ;
    PORT
      LAYER met2 ;
        RECT 191.450 319.240 191.730 319.520 ;
    END
  END imem_axi_wdata_6
  PIN imem_axi_wdata_7
    DIRECTION OUTPUT ;
    USE SIGNAL ;
    ANTENNAGATEAREA 0.434700 ;
    ANTENNADIFFAREA 0.775300 ;
    PORT
      LAYER met2 ;
        RECT 160.170 319.240 160.450 319.520 ;
    END
  END imem_axi_wdata_7
  PIN imem_axi_wdata_8
    DIRECTION OUTPUT ;
    USE SIGNAL ;
    ANTENNAGATEAREA 0.434700 ;
    ANTENNADIFFAREA 0.775300 ;
    PORT
      LAYER met2 ;
        RECT 226.410 319.240 226.690 319.520 ;
    END
  END imem_axi_wdata_8
  PIN imem_axi_wdata_9
    DIRECTION OUTPUT ;
    USE SIGNAL ;
    ANTENNAGATEAREA 0.434700 ;
    ANTENNADIFFAREA 0.775300 ;
    PORT
      LAYER met2 ;
        RECT 147.290 319.240 147.570 319.520 ;
    END
  END imem_axi_wdata_9
  PIN imem_axi_wready
    DIRECTION INPUT ;
    USE SIGNAL ;
    PORT
      LAYER met2 ;
        RECT 11.130 0.000 11.410 0.280 ;
    END
  END imem_axi_wready
  PIN imem_axi_wstrb_0
    DIRECTION OUTPUT ;
    USE SIGNAL ;
    ANTENNAGATEAREA 0.434700 ;
    ANTENNADIFFAREA 0.775300 ;
    PORT
      LAYER met3 ;
        RECT 0.000 148.280 0.600 148.880 ;
    END
  END imem_axi_wstrb_0
  PIN imem_axi_wstrb_1
    DIRECTION OUTPUT ;
    USE SIGNAL ;
    ANTENNAGATEAREA 0.434700 ;
    ANTENNADIFFAREA 0.775300 ;
    PORT
      LAYER met3 ;
        RECT 0.000 152.360 0.600 152.960 ;
    END
  END imem_axi_wstrb_1
  PIN imem_axi_wstrb_2
    DIRECTION OUTPUT ;
    USE SIGNAL ;
    ANTENNAGATEAREA 0.434700 ;
    ANTENNADIFFAREA 0.775300 ;
    PORT
      LAYER met3 ;
        RECT 0.000 156.440 0.600 157.040 ;
    END
  END imem_axi_wstrb_2
  PIN imem_axi_wstrb_3
    DIRECTION OUTPUT ;
    USE SIGNAL ;
    ANTENNAGATEAREA 0.434700 ;
    ANTENNADIFFAREA 0.775300 ;
    PORT
      LAYER met3 ;
        RECT 0.000 122.440 0.600 123.040 ;
    END
  END imem_axi_wstrb_3
  PIN imem_axi_wvalid
    DIRECTION OUTPUT ;
    USE SIGNAL ;
    ANTENNAGATEAREA 0.434700 ;
    ANTENNADIFFAREA 0.775300 ;
    PORT
      LAYER met3 ;
        RECT 0.000 153.720 0.600 154.320 ;
    END
  END imem_axi_wvalid
  PIN imem_rdata_0
    DIRECTION OUTPUT ;
    USE SIGNAL ;
    ANTENNAGATEAREA 0.434700 ;
    ANTENNADIFFAREA 1.137600 ;
    PORT
      LAYER met2 ;
        RECT 149.130 319.240 149.410 319.520 ;
    END
  END imem_rdata_0
  PIN imem_rdata_1
    DIRECTION OUTPUT ;
    USE SIGNAL ;
    ANTENNAGATEAREA 0.434700 ;
    ANTENNADIFFAREA 1.137600 ;
    PORT
      LAYER met2 ;
        RECT 121.530 319.240 121.810 319.520 ;
    END
  END imem_rdata_1
  PIN imem_rdata_10
    DIRECTION OUTPUT ;
    USE SIGNAL ;
    ANTENNAGATEAREA 0.434700 ;
    ANTENNADIFFAREA 1.137600 ;
    PORT
      LAYER met3 ;
        RECT 0.000 182.280 0.600 182.880 ;
    END
  END imem_rdata_10
  PIN imem_rdata_11
    DIRECTION OUTPUT ;
    USE SIGNAL ;
    ANTENNAGATEAREA 0.434700 ;
    ANTENNADIFFAREA 1.137600 ;
    PORT
      LAYER met2 ;
        RECT 137.170 319.240 137.450 319.520 ;
    END
  END imem_rdata_11
  PIN imem_rdata_12
    DIRECTION OUTPUT ;
    USE SIGNAL ;
    ANTENNAGATEAREA 0.434700 ;
    ANTENNADIFFAREA 1.137600 ;
    PORT
      LAYER met2 ;
        RECT 102.210 319.240 102.490 319.520 ;
    END
  END imem_rdata_12
  PIN imem_rdata_13
    DIRECTION OUTPUT ;
    USE SIGNAL ;
    ANTENNAGATEAREA 0.434700 ;
    ANTENNADIFFAREA 1.137600 ;
    PORT
      LAYER met2 ;
        RECT 120.610 319.240 120.890 319.520 ;
    END
  END imem_rdata_13
  PIN imem_rdata_14
    DIRECTION OUTPUT ;
    USE SIGNAL ;
    ANTENNAGATEAREA 0.434700 ;
    ANTENNADIFFAREA 1.137600 ;
    PORT
      LAYER met2 ;
        RECT 159.250 319.240 159.530 319.520 ;
    END
  END imem_rdata_14
  PIN imem_rdata_15
    DIRECTION OUTPUT ;
    USE SIGNAL ;
    ANTENNAGATEAREA 0.434700 ;
    ANTENNADIFFAREA 1.137600 ;
    PORT
      LAYER met2 ;
        RECT 163.850 319.240 164.130 319.520 ;
    END
  END imem_rdata_15
  PIN imem_rdata_16
    DIRECTION OUTPUT ;
    USE SIGNAL ;
    ANTENNAGATEAREA 0.434700 ;
    ANTENNADIFFAREA 1.137600 ;
    PORT
      LAYER met2 ;
        RECT 170.290 319.240 170.570 319.520 ;
    END
  END imem_rdata_16
  PIN imem_rdata_17
    DIRECTION OUTPUT ;
    USE SIGNAL ;
    ANTENNAGATEAREA 0.434700 ;
    ANTENNADIFFAREA 1.137600 ;
    PORT
      LAYER met3 ;
        RECT 0.000 183.640 0.600 184.240 ;
    END
  END imem_rdata_17
  PIN imem_rdata_18
    DIRECTION OUTPUT ;
    USE SIGNAL ;
    ANTENNAGATEAREA 0.434700 ;
    ANTENNADIFFAREA 1.137600 ;
    PORT
      LAYER met2 ;
        RECT 134.410 319.240 134.690 319.520 ;
    END
  END imem_rdata_18
  PIN imem_rdata_19
    DIRECTION OUTPUT ;
    USE SIGNAL ;
    ANTENNAGATEAREA 0.434700 ;
    ANTENNADIFFAREA 1.137600 ;
    PORT
      LAYER met2 ;
        RECT 164.770 319.240 165.050 319.520 ;
    END
  END imem_rdata_19
  PIN imem_rdata_2
    DIRECTION OUTPUT ;
    USE SIGNAL ;
    ANTENNAGATEAREA 0.434700 ;
    ANTENNADIFFAREA 1.137600 ;
    PORT
      LAYER met2 ;
        RECT 106.810 319.240 107.090 319.520 ;
    END
  END imem_rdata_2
  PIN imem_rdata_20
    DIRECTION OUTPUT ;
    USE SIGNAL ;
    ANTENNAGATEAREA 0.434700 ;
    ANTENNADIFFAREA 1.137600 ;
    PORT
      LAYER met2 ;
        RECT 103.130 319.240 103.410 319.520 ;
    END
  END imem_rdata_20
  PIN imem_rdata_21
    DIRECTION OUTPUT ;
    USE SIGNAL ;
    ANTENNAGATEAREA 0.434700 ;
    ANTENNADIFFAREA 1.137600 ;
    PORT
      LAYER met2 ;
        RECT 169.370 319.240 169.650 319.520 ;
    END
  END imem_rdata_21
  PIN imem_rdata_22
    DIRECTION OUTPUT ;
    USE SIGNAL ;
    ANTENNAGATEAREA 0.434700 ;
    ANTENNADIFFAREA 1.137600 ;
    PORT
      LAYER met2 ;
        RECT 151.890 319.240 152.170 319.520 ;
    END
  END imem_rdata_22
  PIN imem_rdata_23
    DIRECTION OUTPUT ;
    USE SIGNAL ;
    ANTENNAGATEAREA 0.434700 ;
    ANTENNADIFFAREA 1.137600 ;
    PORT
      LAYER met3 ;
        RECT 0.000 219.000 0.600 219.600 ;
    END
  END imem_rdata_23
  PIN imem_rdata_24
    DIRECTION OUTPUT ;
    USE SIGNAL ;
    ANTENNAGATEAREA 0.434700 ;
    ANTENNADIFFAREA 1.137600 ;
    PORT
      LAYER met3 ;
        RECT 0.000 217.640 0.600 218.240 ;
    END
  END imem_rdata_24
  PIN imem_rdata_25
    DIRECTION OUTPUT ;
    USE SIGNAL ;
    ANTENNAGATEAREA 0.434700 ;
    ANTENNADIFFAREA 1.137600 ;
    PORT
      LAYER met3 ;
        RECT 0.000 206.760 0.600 207.360 ;
    END
  END imem_rdata_25
  PIN imem_rdata_26
    DIRECTION OUTPUT ;
    USE SIGNAL ;
    ANTENNAGATEAREA 0.434700 ;
    ANTENNADIFFAREA 1.137600 ;
    PORT
      LAYER met3 ;
        RECT 0.000 225.800 0.600 226.400 ;
    END
  END imem_rdata_26
  PIN imem_rdata_27
    DIRECTION OUTPUT ;
    USE SIGNAL ;
    ANTENNAGATEAREA 0.434700 ;
    ANTENNADIFFAREA 1.137600 ;
    PORT
      LAYER met2 ;
        RECT 138.090 319.240 138.370 319.520 ;
    END
  END imem_rdata_27
  PIN imem_rdata_28
    DIRECTION OUTPUT ;
    USE SIGNAL ;
    ANTENNAGATEAREA 0.434700 ;
    ANTENNADIFFAREA 1.137600 ;
    PORT
      LAYER met3 ;
        RECT 0.000 212.200 0.600 212.800 ;
    END
  END imem_rdata_28
  PIN imem_rdata_29
    DIRECTION OUTPUT ;
    USE SIGNAL ;
    ANTENNAGATEAREA 0.434700 ;
    ANTENNADIFFAREA 1.137600 ;
    PORT
      LAYER met3 ;
        RECT 0.000 167.320 0.600 167.920 ;
    END
  END imem_rdata_29
  PIN imem_rdata_3
    DIRECTION OUTPUT ;
    USE SIGNAL ;
    ANTENNAGATEAREA 0.434700 ;
    ANTENNADIFFAREA 1.137600 ;
    PORT
      LAYER met2 ;
        RECT 143.610 319.240 143.890 319.520 ;
    END
  END imem_rdata_3
  PIN imem_rdata_30
    DIRECTION OUTPUT ;
    USE SIGNAL ;
    ANTENNAGATEAREA 0.434700 ;
    ANTENNADIFFAREA 1.137600 ;
    PORT
      LAYER met3 ;
        RECT 0.000 170.040 0.600 170.640 ;
    END
  END imem_rdata_30
  PIN imem_rdata_31
    DIRECTION OUTPUT ;
    USE SIGNAL ;
    ANTENNAGATEAREA 0.434700 ;
    ANTENNADIFFAREA 1.137600 ;
    PORT
      LAYER met3 ;
        RECT 0.000 131.960 0.600 132.560 ;
    END
  END imem_rdata_31
  PIN imem_rdata_4
    DIRECTION OUTPUT ;
    USE SIGNAL ;
    ANTENNAGATEAREA 0.434700 ;
    ANTENNADIFFAREA 1.137600 ;
    PORT
      LAYER met3 ;
        RECT 0.000 198.600 0.600 199.200 ;
    END
  END imem_rdata_4
  PIN imem_rdata_5
    DIRECTION OUTPUT ;
    USE SIGNAL ;
    ANTENNAGATEAREA 0.434700 ;
    ANTENNADIFFAREA 1.137600 ;
    PORT
      LAYER met3 ;
        RECT 0.000 190.440 0.600 191.040 ;
    END
  END imem_rdata_5
  PIN imem_rdata_6
    DIRECTION OUTPUT ;
    USE SIGNAL ;
    ANTENNAGATEAREA 0.434700 ;
    ANTENNADIFFAREA 1.137600 ;
    PORT
      LAYER met2 ;
        RECT 122.450 319.240 122.730 319.520 ;
    END
  END imem_rdata_6
  PIN imem_rdata_7
    DIRECTION OUTPUT ;
    USE SIGNAL ;
    ANTENNAGATEAREA 0.434700 ;
    ANTENNADIFFAREA 1.137600 ;
    PORT
      LAYER met2 ;
        RECT 145.450 319.240 145.730 319.520 ;
    END
  END imem_rdata_7
  PIN imem_rdata_8
    DIRECTION OUTPUT ;
    USE SIGNAL ;
    ANTENNAGATEAREA 0.434700 ;
    ANTENNADIFFAREA 1.137600 ;
    PORT
      LAYER met2 ;
        RECT 108.650 319.240 108.930 319.520 ;
    END
  END imem_rdata_8
  PIN imem_rdata_9
    DIRECTION OUTPUT ;
    USE SIGNAL ;
    ANTENNAGATEAREA 0.434700 ;
    ANTENNADIFFAREA 1.137600 ;
    PORT
      LAYER met2 ;
        RECT 142.690 319.240 142.970 319.520 ;
    END
  END imem_rdata_9
  PIN imem_ready
    DIRECTION OUTPUT ;
    USE SIGNAL ;
    ANTENNAGATEAREA 0.434700 ;
    ANTENNADIFFAREA 1.137600 ;
    PORT
      LAYER met3 ;
        RECT 308.200 165.960 308.800 166.560 ;
    END
  END imem_ready
  PIN imem_req
    DIRECTION INPUT ;
    USE SIGNAL ;
    ANTENNAGATEAREA 0.647700 ;
    ANTENNADIFFAREA 0.434700 ;
    PORT
      LAYER met3 ;
        RECT 0.000 171.400 0.600 172.000 ;
    END
  END imem_req
  PIN rst_n
    DIRECTION INPUT ;
    USE SIGNAL ;
    ANTENNAGATEAREA 0.647700 ;
    ANTENNADIFFAREA 0.434700 ;
    PORT
      LAYER met3 ;
        RECT 0.000 258.440 0.600 259.040 ;
    END
  END rst_n
  OBS
      LAYER nwell ;
        RECT 5.330 10.795 303.330 307.550 ;
      LAYER li1 ;
        RECT 5.520 10.795 303.140 307.445 ;
      LAYER met1 ;
        RECT 5.520 10.240 303.140 307.600 ;
      LAYER met2 ;
        RECT 5.610 318.960 22.810 319.240 ;
        RECT 23.650 318.960 32.930 319.240 ;
        RECT 33.770 318.960 34.770 319.240 ;
        RECT 35.610 318.960 36.610 319.240 ;
        RECT 37.450 318.960 37.530 319.240 ;
        RECT 38.370 318.960 38.450 319.240 ;
        RECT 39.290 318.960 40.290 319.240 ;
        RECT 41.130 318.960 55.010 319.240 ;
        RECT 55.850 318.960 56.850 319.240 ;
        RECT 57.690 318.960 65.130 319.240 ;
        RECT 65.970 318.960 66.050 319.240 ;
        RECT 66.890 318.960 66.970 319.240 ;
        RECT 67.810 318.960 67.890 319.240 ;
        RECT 68.730 318.960 73.410 319.240 ;
        RECT 74.250 318.960 75.250 319.240 ;
        RECT 76.090 318.960 78.010 319.240 ;
        RECT 78.850 318.960 78.930 319.240 ;
        RECT 79.770 318.960 81.690 319.240 ;
        RECT 82.530 318.960 82.610 319.240 ;
        RECT 83.450 318.960 83.530 319.240 ;
        RECT 84.370 318.960 85.370 319.240 ;
        RECT 86.210 318.960 101.930 319.240 ;
        RECT 102.770 318.960 102.850 319.240 ;
        RECT 103.690 318.960 103.770 319.240 ;
        RECT 104.610 318.960 104.690 319.240 ;
        RECT 105.530 318.960 105.610 319.240 ;
        RECT 106.450 318.960 106.530 319.240 ;
        RECT 107.370 318.960 107.450 319.240 ;
        RECT 108.290 318.960 108.370 319.240 ;
        RECT 109.210 318.960 117.570 319.240 ;
        RECT 118.410 318.960 118.490 319.240 ;
        RECT 119.330 318.960 119.410 319.240 ;
        RECT 120.250 318.960 120.330 319.240 ;
        RECT 121.170 318.960 121.250 319.240 ;
        RECT 122.090 318.960 122.170 319.240 ;
        RECT 123.010 318.960 132.290 319.240 ;
        RECT 133.130 318.960 133.210 319.240 ;
        RECT 134.050 318.960 134.130 319.240 ;
        RECT 134.970 318.960 135.050 319.240 ;
        RECT 135.890 318.960 135.970 319.240 ;
        RECT 136.810 318.960 136.890 319.240 ;
        RECT 137.730 318.960 137.810 319.240 ;
        RECT 138.650 318.960 138.730 319.240 ;
        RECT 139.570 318.960 139.650 319.240 ;
        RECT 140.490 318.960 140.570 319.240 ;
        RECT 141.410 318.960 141.490 319.240 ;
        RECT 142.330 318.960 142.410 319.240 ;
        RECT 143.250 318.960 143.330 319.240 ;
        RECT 144.170 318.960 144.250 319.240 ;
        RECT 145.090 318.960 145.170 319.240 ;
        RECT 146.010 318.960 146.090 319.240 ;
        RECT 146.930 318.960 147.010 319.240 ;
        RECT 147.850 318.960 147.930 319.240 ;
        RECT 148.770 318.960 148.850 319.240 ;
        RECT 149.690 318.960 149.770 319.240 ;
        RECT 150.610 318.960 150.690 319.240 ;
        RECT 151.530 318.960 151.610 319.240 ;
        RECT 152.450 318.960 152.530 319.240 ;
        RECT 153.370 318.960 153.450 319.240 ;
        RECT 154.290 318.960 154.370 319.240 ;
        RECT 155.210 318.960 155.290 319.240 ;
        RECT 156.130 318.960 156.210 319.240 ;
        RECT 157.050 318.960 157.130 319.240 ;
        RECT 157.970 318.960 158.050 319.240 ;
        RECT 158.890 318.960 158.970 319.240 ;
        RECT 159.810 318.960 159.890 319.240 ;
        RECT 160.730 318.960 160.810 319.240 ;
        RECT 161.650 318.960 161.730 319.240 ;
        RECT 162.570 318.960 162.650 319.240 ;
        RECT 163.490 318.960 163.570 319.240 ;
        RECT 164.410 318.960 164.490 319.240 ;
        RECT 165.330 318.960 165.410 319.240 ;
        RECT 166.250 318.960 166.330 319.240 ;
        RECT 167.170 318.960 167.250 319.240 ;
        RECT 168.090 318.960 168.170 319.240 ;
        RECT 169.010 318.960 169.090 319.240 ;
        RECT 169.930 318.960 170.010 319.240 ;
        RECT 170.850 318.960 170.930 319.240 ;
        RECT 171.770 318.960 171.850 319.240 ;
        RECT 172.690 318.960 172.770 319.240 ;
        RECT 173.610 318.960 173.690 319.240 ;
        RECT 174.530 318.960 174.610 319.240 ;
        RECT 175.450 318.960 175.530 319.240 ;
        RECT 176.370 318.960 176.450 319.240 ;
        RECT 177.290 318.960 177.370 319.240 ;
        RECT 178.210 318.960 178.290 319.240 ;
        RECT 179.130 318.960 179.210 319.240 ;
        RECT 180.050 318.960 180.130 319.240 ;
        RECT 180.970 318.960 181.050 319.240 ;
        RECT 181.890 318.960 181.970 319.240 ;
        RECT 182.810 318.960 182.890 319.240 ;
        RECT 183.730 318.960 183.810 319.240 ;
        RECT 184.650 318.960 184.730 319.240 ;
        RECT 185.570 318.960 185.650 319.240 ;
        RECT 186.490 318.960 186.570 319.240 ;
        RECT 187.410 318.960 187.490 319.240 ;
        RECT 188.330 318.960 188.410 319.240 ;
        RECT 189.250 318.960 189.330 319.240 ;
        RECT 190.170 318.960 190.250 319.240 ;
        RECT 191.090 318.960 191.170 319.240 ;
        RECT 192.010 318.960 192.090 319.240 ;
        RECT 192.930 318.960 193.010 319.240 ;
        RECT 193.850 318.960 193.930 319.240 ;
        RECT 194.770 318.960 194.850 319.240 ;
        RECT 195.690 318.960 195.770 319.240 ;
        RECT 196.610 318.960 196.690 319.240 ;
        RECT 197.530 318.960 197.610 319.240 ;
        RECT 198.450 318.960 198.530 319.240 ;
        RECT 199.370 318.960 199.450 319.240 ;
        RECT 200.290 318.960 200.370 319.240 ;
        RECT 201.210 318.960 201.290 319.240 ;
        RECT 202.130 318.960 202.210 319.240 ;
        RECT 203.050 318.960 203.130 319.240 ;
        RECT 203.970 318.960 204.050 319.240 ;
        RECT 204.890 318.960 204.970 319.240 ;
        RECT 205.810 318.960 205.890 319.240 ;
        RECT 206.730 318.960 206.810 319.240 ;
        RECT 207.650 318.960 207.730 319.240 ;
        RECT 208.570 318.960 208.650 319.240 ;
        RECT 209.490 318.960 209.570 319.240 ;
        RECT 210.410 318.960 210.490 319.240 ;
        RECT 211.330 318.960 211.410 319.240 ;
        RECT 212.250 318.960 212.330 319.240 ;
        RECT 213.170 318.960 213.250 319.240 ;
        RECT 214.090 318.960 214.170 319.240 ;
        RECT 215.010 318.960 215.090 319.240 ;
        RECT 215.930 318.960 216.010 319.240 ;
        RECT 216.850 318.960 216.930 319.240 ;
        RECT 217.770 318.960 217.850 319.240 ;
        RECT 218.690 318.960 218.770 319.240 ;
        RECT 219.610 318.960 219.690 319.240 ;
        RECT 220.530 318.960 220.610 319.240 ;
        RECT 221.450 318.960 221.530 319.240 ;
        RECT 222.370 318.960 222.450 319.240 ;
        RECT 223.290 318.960 223.370 319.240 ;
        RECT 224.210 318.960 224.290 319.240 ;
        RECT 225.130 318.960 225.210 319.240 ;
        RECT 226.050 318.960 226.130 319.240 ;
        RECT 226.970 318.960 227.050 319.240 ;
        RECT 227.890 318.960 227.970 319.240 ;
        RECT 228.810 318.960 228.890 319.240 ;
        RECT 229.730 318.960 231.650 319.240 ;
        RECT 232.490 318.960 233.490 319.240 ;
        RECT 234.330 318.960 234.410 319.240 ;
        RECT 235.250 318.960 236.250 319.240 ;
        RECT 237.090 318.960 237.170 319.240 ;
        RECT 238.010 318.960 238.090 319.240 ;
        RECT 238.930 318.960 241.770 319.240 ;
        RECT 242.610 318.960 243.610 319.240 ;
        RECT 244.450 318.960 244.530 319.240 ;
        RECT 245.370 318.960 247.290 319.240 ;
        RECT 248.130 318.960 249.130 319.240 ;
        RECT 249.970 318.960 303.050 319.240 ;
        RECT 5.610 0.560 303.050 318.960 ;
        RECT 6.170 0.280 6.250 0.560 ;
        RECT 7.090 0.280 7.170 0.560 ;
        RECT 8.010 0.280 8.090 0.560 ;
        RECT 8.930 0.280 9.010 0.560 ;
        RECT 9.850 0.280 9.930 0.560 ;
        RECT 10.770 0.280 10.850 0.560 ;
        RECT 11.690 0.280 66.050 0.560 ;
        RECT 66.890 0.280 66.970 0.560 ;
        RECT 67.810 0.280 67.890 0.560 ;
        RECT 68.730 0.280 68.810 0.560 ;
        RECT 69.650 0.280 69.730 0.560 ;
        RECT 70.570 0.280 70.650 0.560 ;
        RECT 71.490 0.280 71.570 0.560 ;
        RECT 72.410 0.280 72.490 0.560 ;
        RECT 73.330 0.280 73.410 0.560 ;
        RECT 74.250 0.280 74.330 0.560 ;
        RECT 75.170 0.280 75.250 0.560 ;
        RECT 76.090 0.280 76.170 0.560 ;
        RECT 77.010 0.280 77.090 0.560 ;
        RECT 77.930 0.280 78.010 0.560 ;
        RECT 78.850 0.280 78.930 0.560 ;
        RECT 79.770 0.280 79.850 0.560 ;
        RECT 80.690 0.280 80.770 0.560 ;
        RECT 81.610 0.280 81.690 0.560 ;
        RECT 82.530 0.280 90.890 0.560 ;
        RECT 91.730 0.280 91.810 0.560 ;
        RECT 92.650 0.280 92.730 0.560 ;
        RECT 93.570 0.280 102.850 0.560 ;
        RECT 103.690 0.280 103.770 0.560 ;
        RECT 104.610 0.280 104.690 0.560 ;
        RECT 105.530 0.280 105.610 0.560 ;
        RECT 106.450 0.280 106.530 0.560 ;
        RECT 107.370 0.280 107.450 0.560 ;
        RECT 108.290 0.280 108.370 0.560 ;
        RECT 109.210 0.280 109.290 0.560 ;
        RECT 110.130 0.280 110.210 0.560 ;
        RECT 111.050 0.280 111.130 0.560 ;
        RECT 111.970 0.280 112.050 0.560 ;
        RECT 112.890 0.280 112.970 0.560 ;
        RECT 113.810 0.280 113.890 0.560 ;
        RECT 114.730 0.280 114.810 0.560 ;
        RECT 115.650 0.280 115.730 0.560 ;
        RECT 116.570 0.280 118.490 0.560 ;
        RECT 119.330 0.280 119.410 0.560 ;
        RECT 120.250 0.280 120.330 0.560 ;
        RECT 121.170 0.280 122.170 0.560 ;
        RECT 123.010 0.280 123.090 0.560 ;
        RECT 123.930 0.280 124.010 0.560 ;
        RECT 124.850 0.280 136.890 0.560 ;
        RECT 137.730 0.280 137.810 0.560 ;
        RECT 138.650 0.280 138.730 0.560 ;
        RECT 139.570 0.280 139.650 0.560 ;
        RECT 140.490 0.280 140.570 0.560 ;
        RECT 141.410 0.280 141.490 0.560 ;
        RECT 142.330 0.280 142.410 0.560 ;
        RECT 143.250 0.280 143.330 0.560 ;
        RECT 144.170 0.280 144.250 0.560 ;
        RECT 145.090 0.280 145.170 0.560 ;
        RECT 146.010 0.280 146.090 0.560 ;
        RECT 146.930 0.280 147.010 0.560 ;
        RECT 147.850 0.280 147.930 0.560 ;
        RECT 148.770 0.280 148.850 0.560 ;
        RECT 149.690 0.280 149.770 0.560 ;
        RECT 150.610 0.280 152.530 0.560 ;
        RECT 153.370 0.280 153.450 0.560 ;
        RECT 154.290 0.280 154.370 0.560 ;
        RECT 155.210 0.280 185.650 0.560 ;
        RECT 186.490 0.280 186.570 0.560 ;
        RECT 187.410 0.280 187.490 0.560 ;
        RECT 188.330 0.280 188.410 0.560 ;
        RECT 189.250 0.280 189.330 0.560 ;
        RECT 190.170 0.280 190.250 0.560 ;
        RECT 191.090 0.280 191.170 0.560 ;
        RECT 192.010 0.280 192.090 0.560 ;
        RECT 192.930 0.280 193.010 0.560 ;
        RECT 193.850 0.280 193.930 0.560 ;
        RECT 194.770 0.280 194.850 0.560 ;
        RECT 195.690 0.280 195.770 0.560 ;
        RECT 196.610 0.280 196.690 0.560 ;
        RECT 197.530 0.280 197.610 0.560 ;
        RECT 198.450 0.280 198.530 0.560 ;
        RECT 199.370 0.280 199.450 0.560 ;
        RECT 200.290 0.280 200.370 0.560 ;
        RECT 201.210 0.280 201.290 0.560 ;
        RECT 202.130 0.280 209.570 0.560 ;
        RECT 210.410 0.280 210.490 0.560 ;
        RECT 211.330 0.280 211.410 0.560 ;
        RECT 212.250 0.280 212.330 0.560 ;
        RECT 213.170 0.280 213.250 0.560 ;
        RECT 214.090 0.280 214.170 0.560 ;
        RECT 215.010 0.280 215.090 0.560 ;
        RECT 215.930 0.280 216.010 0.560 ;
        RECT 216.850 0.280 216.930 0.560 ;
        RECT 217.770 0.280 217.850 0.560 ;
        RECT 218.690 0.280 218.770 0.560 ;
        RECT 219.610 0.280 219.690 0.560 ;
        RECT 220.530 0.280 220.610 0.560 ;
        RECT 221.450 0.280 221.530 0.560 ;
        RECT 222.370 0.280 232.570 0.560 ;
        RECT 233.410 0.280 233.490 0.560 ;
        RECT 234.330 0.280 235.330 0.560 ;
        RECT 236.170 0.280 236.250 0.560 ;
        RECT 237.090 0.280 246.370 0.560 ;
        RECT 247.210 0.280 247.290 0.560 ;
        RECT 248.130 0.280 248.210 0.560 ;
        RECT 249.050 0.280 249.130 0.560 ;
        RECT 249.970 0.280 250.050 0.560 ;
        RECT 250.890 0.280 250.970 0.560 ;
        RECT 251.810 0.280 251.890 0.560 ;
        RECT 252.730 0.280 252.810 0.560 ;
        RECT 253.650 0.280 269.370 0.560 ;
        RECT 270.210 0.280 270.290 0.560 ;
        RECT 271.130 0.280 274.890 0.560 ;
        RECT 275.730 0.280 275.810 0.560 ;
        RECT 276.650 0.280 276.730 0.560 ;
        RECT 277.570 0.280 277.650 0.560 ;
        RECT 278.490 0.280 303.050 0.560 ;
      LAYER met3 ;
        RECT 0.600 294.800 308.200 311.945 ;
        RECT 0.600 273.000 307.800 294.800 ;
        RECT 0.600 262.160 308.200 273.000 ;
        RECT 1.000 258.040 308.200 262.160 ;
        RECT 0.600 244.480 308.200 258.040 ;
        RECT 1.000 215.920 308.200 244.480 ;
        RECT 1.000 213.160 307.800 215.920 ;
        RECT 1.000 211.840 308.200 213.160 ;
        RECT 1.000 210.440 307.800 211.840 ;
        RECT 1.000 205.040 308.200 210.440 ;
        RECT 1.000 202.280 307.800 205.040 ;
        RECT 1.000 191.440 308.200 202.280 ;
        RECT 1.000 162.840 307.800 191.440 ;
        RECT 1.000 160.160 308.200 162.840 ;
        RECT 1.000 120.680 307.800 160.160 ;
        RECT 0.600 98.920 307.800 120.680 ;
        RECT 0.600 96.240 308.200 98.920 ;
        RECT 0.600 90.760 307.800 96.240 ;
        RECT 0.600 79.920 308.200 90.760 ;
        RECT 0.600 77.160 307.800 79.920 ;
        RECT 0.600 73.120 308.200 77.160 ;
        RECT 0.600 70.360 307.800 73.120 ;
        RECT 0.600 10.715 308.200 70.360 ;
      LAYER met4 ;
        RECT 26.975 308.000 185.545 311.945 ;
        RECT 26.975 34.175 174.240 308.000 ;
        RECT 176.640 34.175 177.540 308.000 ;
        RECT 179.940 34.175 185.545 308.000 ;
  END
END cpu_axi_master
END LIBRARY

